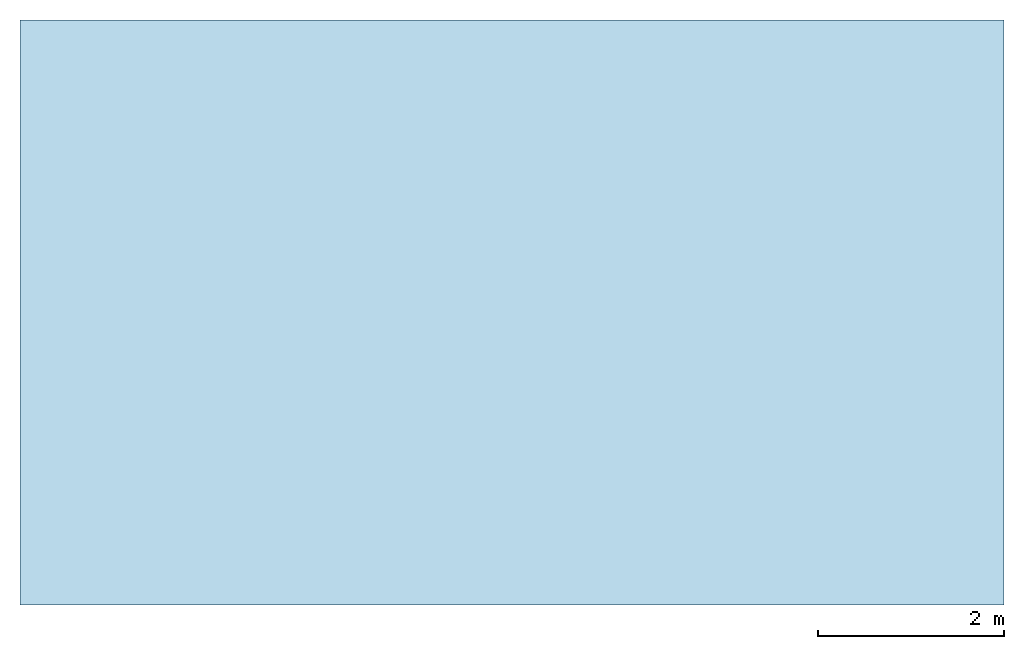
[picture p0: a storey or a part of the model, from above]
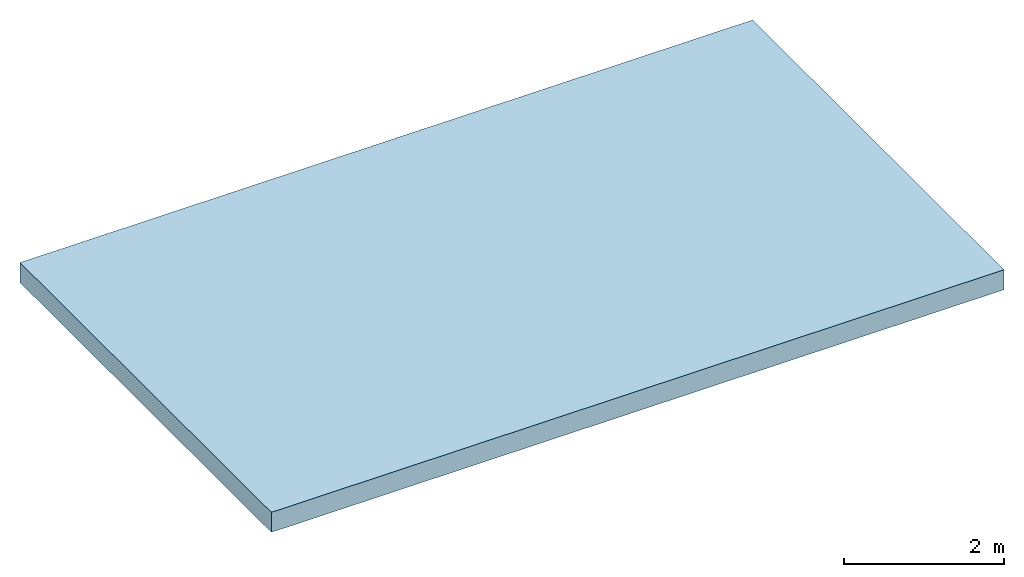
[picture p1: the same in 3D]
Properties of the parts of a building model (IFC2X3), part 1 of 2

# File
Description: ViewDefinition [CoordinationView_V2.0]
File name: Project Number
Time: 2019-01-10T09:33:45
Written by: The EXPRESS Data Manager Version 5.02.0100.07 : 28 Aug 2013
Made in: 20180216_1515(x64) - Exporter 19.0.0.405 - Alternate UI 19.0.0.405
Comment: STEP Physical File produced by: The EXPRESS Data Manager Version 5.02.0100.07 : 28 Aug 2013 * Module: EDMstepFileFactory/EDMstandAlone * Creation date: Thu Jan 10 09:33:45 2019 * Host: nimbus * Database: C:\Users\okonski\AppData\Local\Temp\{17E0146B-8E79-4994-994E-66D10485D688}\ifc * Database version: 5507 * Database creation date: Thu Jan 10 09:33:31 2019 * Schema: IFC2X3 * Model: DataRepository.ifc * Model creation date: Thu Jan 10 09:33:31 2019 * Header model: DataRepository.ifc_HeaderModel * Header model creation date: Thu Jan 10 09:33:31 2019 * EDMuser: sdai-user * EDMgroup: sdai-group * License ID and type: 5605 : Permanent license. Expiry date: * EDMstepFileFactory options: 020000

# IfcProject, Project Number
LongName: Project Name; Phase: Project Status

# IfcSite, Default
RefLatitude: 42, 21, 30, 344238; RefLongitude: -71, -3, -35, -194702; RefElevation: 0 ft

# IfcBuilding
Pset_BuildingCommon - NumberOfStoreys: 14

# IfcBuildingStorey (14)
Name | LongName | Elevation (ft)
Level 1 | Level 1 | 0
L 1 | L 1 | 5
Level 2 | Level 2 | 10
L 2 | L 2 | 15
L 3 | L 3 | 20
L 4 | L 4 | 25
L 5 | L 5 | 30
L 6 | L 6 | 35
L 7 | L 7 | 40
L 8 | L 8 | 45
L 9 | L 9 | 50
L 10 | L 10 | 55
L 11 | L 11 | 60
L 12 | L 12 | 69

# IfcBuildingElementProxy: 36" x 84" (36)
Type - Material: Door - Frame
Pset_BuildingElementProxyCommon - Reference: 36" x 84"
Name (Passage Opening-Cased:36" x 84":...) | In
199862 | Level 1
199918 | Level 1
199949 | Level 1
199975 | Level 1
199997 | Level 1
200042 | Level 1
202377 | Level 2
202378 | Level 2
202379 | Level 2
202380 | Level 2
202381 | Level 2
202382 | Level 2
204046 | L 3
204047 | L 3
204048 | L 3
204049 | L 3
204050 | L 3
204051 | L 3
204783 | L 5
204784 | L 5
204785 | L 5
204786 | L 5
204787 | L 5
204788 | L 5
205241 | L 7
205242 | L 7
205243 | L 7
205244 | L 7
205245 | L 7
205246 | L 7
205681 | L 9
205682 | L 9
205683 | L 9
205684 | L 9
205685 | L 9
205686 | L 9

# IfcColumn: 06" Diameter (2)
In: Level 1
Type - ElementType: 06" Diameter; PredefinedType: COLUMN; Classification: B1010200 Upper Floor Framing - Vertical Elements (Uniformat)
Pset_ColumnCommon - IsExternal: no; LoadBearing: no; Reference: 06" Diameter
Name (Round Column:06" Diameter:...)
209231 | Pset_ColumnCommon - Slope: 0 deg
209550

# IfcCurtainWall: Curtain Wall:Storefront, Curtain Wall:Storefront:194278
In: Level 1
Classification: B2020200 Curtain Walls (Uniformat)
Pset_CurtainWallCommon - IsExternal: yes; Reference: Storefront

# IfcCurtainWall: Curtain Wall:Storefront 2 (56)
Classification: B2020200 Curtain Walls (Uniformat)
Pset_CurtainWallCommon - IsExternal: yes; Reference: Storefront 2
Name (Curtain Wall:Storefront 2:...) | In | Group
196427 | Level 1 | Model Group:Group 3:200611
196767 | Level 1 | Model Group:Group 3:200611
196928 | Level 1 | Model Group:Group 3:200611
197503 | Level 1 | Model Group:Group 3:200611
197879 | Level 1 | Model Group:Group 3:200611
198087 | Level 1 | Model Group:Group 3:200611
198260 | Level 1 | Model Group:Group 3:200611
200148 | Level 1 | Model Group:Group 3:200611
200336 | Level 1 | Model Group:Group 3:200611
201495 | Level 2 | Model Group:Group 4:201905
201521 | Level 2 | Model Group:Group 4:201905
201547 | Level 2 | Model Group:Group 4:201905
201573 | Level 2 | Model Group:Group 4:201905
201599 | Level 2 | Model Group:Group 4:201905
201682 | Level 2 | Model Group:Group 4:201905
201717 | Level 2 | Model Group:Group 4:201905
201844 | Level 2 | Model Group:Group 4:201905
201879 | Level 2 | Model Group:Group 4:201905
203661 | L 3 | Model Group:Group 4:204045
203686 | L 3 | Model Group:Group 4:204045
203711 | L 3 | Model Group:Group 4:204045
203737 | L 3 | Model Group:Group 4:204045
203763 | L 3 | Model Group:Group 4:204045
203846 | L 3 | Model Group:Group 4:204045
203880 | L 3 | Model Group:Group 4:204045
203985 | L 3 | Model Group:Group 4:204045
204019 | L 3 | Model Group:Group 4:204045
204398 | L 5 | Model Group:Group 4:204782
204423 | L 5 | Model Group:Group 4:204782
204448 | L 5 | Model Group:Group 4:204782
204474 | L 5 | Model Group:Group 4:204782
204500 | L 5 | Model Group:Group 4:204782
204583 | L 5 | Model Group:Group 4:204782
204617 | L 5 | Model Group:Group 4:204782
204722 | L 5 | Model Group:Group 4:204782
204756 | L 5 | Model Group:Group 4:204782
204856 | L 7 | Model Group:Group 4:205240
204881 | L 7 | Model Group:Group 4:205240
204906 | L 7 | Model Group:Group 4:205240
204932 | L 7 | Model Group:Group 4:205240
204958 | L 7 | Model Group:Group 4:205240
205041 | L 7 | Model Group:Group 4:205240
205075 | L 7 | Model Group:Group 4:205240
205180 | L 7 | Model Group:Group 4:205240
205214 | L 7 | Model Group:Group 4:205240
205296 | L 9
205321 | L 9
205346 | L 9 | Model Group:Array Group 2:207312
205372 | L 9 | Model Group:Array Group 2:207312
205398 | L 9
205481 | L 9
205515 | L 9
205620 | L 9
205654 | L 9
207315 | L 11
207341 | L 11

# IfcGroup: Model Group:Group 4 (4)
Name (Model Group:Group 4:...) | Group
201905
204045 | Model Group:Array Group 1:204379
204782 | Model Group:Array Group 1:204817
205240 | Model Group:Array Group 1:205275

# IfcMember: 2.5" x 5" rectangular (1532)
Type - ElementType: 2.5" x 5" rectangular; PredefinedType: MEMBER
Classification: B2020200 Curtain Walls (Uniformat); Material: Aluminum
Pset_MemberCommon - LoadBearing: yes; IsExternal: yes; Reference: 2.5" x 5" rectangular
Name (Rectangular Mullion:2.5" x 5" rectangular:...) | In | Span (ft) | Group
194291 | Level 1 | 4.6875
194292 | Level 1 | 4.6875
194293 | Level 1 | 4.6875
194294 | Level 1 | 4.6875
194295 | Level 1 | 5
194296 | Level 1 | 5
194297 | Level 1 | 5
194298 | Level 1 | 3
194299 | Level 1 | 5
194300 | Level 1 | 5
194301 | Level 1 | 4.6875
194302 | Level 1 | 4.6875
194303 | Level 1 | 4.6875
194304 | Level 1 | 4.6875
194305 | Level 1 | 5
194306 | Level 1 | 5
194307 | Level 1 | 5
194373 | Level 1 | 5
194374 | Level 1 | 5
194375 | Level 1 | 5
194376 | Level 1 | 5
194377 | Level 1 | 5
194378 | Level 1 | 5
194379 | Level 1 | 5
194380 | Level 1 | 5
194381 | Level 1 | 5
194382 | Level 1 | 5
194383 | Level 1 | 5
194384 | Level 1 | 5
194385 | Level 1 | 5
194386 | Level 1 | 5
194387 | Level 1 | 5
194388 | Level 1 | 4.6875
194389 | Level 1 | 4.6875
194390 | Level 1 | 4.6875
194391 | Level 1 | 4.6875
194392 | Level 1 | 4.6875
194393 | Level 1 | 4.6875
194394 | Level 1 | 4.6875
194395 | Level 1 | 4.6875
194396 | Level 1 | 4.6875
194397 | Level 1 | 4.6875
194475 | Level 1 | 5
194476 | Level 1 | 5
194477 | Level 1 | 5
194478 | Level 1 | 5
194479 | Level 1 | 5
194480 | Level 1 | 5
194481 | Level 1 | 5
194482 | Level 1 | 5
194483 | Level 1 | 5
194484 | Level 1 | 5
194485 | Level 1 | 5
194486 | Level 1 | 5
194487 | Level 1 | 4.6875
194488 | Level 1 | 4.6875
194489 | Level 1 | 4.6875
194490 | Level 1 | 4.6875
194491 | Level 1 | 4.6875
194492 | Level 1 | 4.6875
194493 | Level 1 | 4.6875
194494 | Level 1 | 4.6875
206421 | Level 1 | 5
206422 | Level 1 | 5
206423 | Level 1 | 5
206424 | Level 1 | 3
206425 | Level 1 | 5
206426 | Level 1 | 3
206427 | Level 1 | 4.6875
206428 | Level 1 | 4.6875
206429 | Level 1 | 4.6875
206430 | Level 1 | 4.6875
196453 | Level 1 | 4.6875 | Model Group:Group 3:200611
196454 | Level 1 | 4.6875 | Model Group:Group 3:200611
196455 | Level 1 | 4.79167 | Model Group:Group 3:200611
196457 | Level 1 | 4.6875 | Model Group:Group 3:200611
196459 | Level 1 | 4.6875 | Model Group:Group 3:200611
196461 | Level 1 | 7 | Model Group:Group 3:200611
196462 | Level 1 | 2 | Model Group:Group 3:200611
196465 | Level 1 | 2 | Model Group:Group 3:200611
196466 | Level 1 | 7 | Model Group:Group 3:200611
196469 | Level 1 | 4.6875 | Model Group:Group 3:200611
196470 | Level 1 | 4.79167 | Model Group:Group 3:200611
196471 | Level 1 | 4.6875 | Model Group:Group 3:200611
196481 | Level 1 | 7 | Model Group:Group 3:200611
196482 | Level 1 | 7 | Model Group:Group 3:200611
196484 | Level 1 | 2 | Model Group:Group 3:200611
196485 | Level 1 | 2 | Model Group:Group 3:200611
196777 | Level 1 | 4.6875 | Model Group:Group 3:200611
196778 | Level 1 | 4.6875 | Model Group:Group 3:200611
196779 | Level 1 | 4.79167 | Model Group:Group 3:200611
196780 | Level 1 | 4.6875 | Model Group:Group 3:200611
196781 | Level 1 | 4.6875 | Model Group:Group 3:200611
196782 | Level 1 | 7 | Model Group:Group 3:200611
196783 | Level 1 | 2 | Model Group:Group 3:200611
196784 | Level 1 | 2 | Model Group:Group 3:200611
196785 | Level 1 | 7 | Model Group:Group 3:200611
196786 | Level 1 | 4.6875 | Model Group:Group 3:200611
196787 | Level 1 | 4.79167 | Model Group:Group 3:200611
196788 | Level 1 | 4.6875 | Model Group:Group 3:200611
196789 | Level 1 | 7 | Model Group:Group 3:200611
196790 | Level 1 | 7 | Model Group:Group 3:200611
196791 | Level 1 | 2 | Model Group:Group 3:200611
196792 | Level 1 | 2 | Model Group:Group 3:200611
196941 | Level 1 | 0.604167 | Model Group:Group 3:200611
196942 | Level 1 | 0.604167 | Model Group:Group 3:200611
196943 | Level 1 | 7 | Model Group:Group 3:200611
196944 | Level 1 | 2 | Model Group:Group 3:200611
196947 | Level 1 | 2 | Model Group:Group 3:200611
196948 | Level 1 | 7 | Model Group:Group 3:200611
196951 | Level 1 | 0.604167 | Model Group:Group 3:200611
197210 | Level 1 | 0.604167 | Model Group:Group 3:200611
197212 | Level 1 | 2.79167 | Model Group:Group 3:200611
197213 | Level 1 | 7 | Model Group:Group 3:200611
197214 | Level 1 | 2 | Model Group:Group 3:200611
197342 | Level 1 | 2.79167 | Model Group:Group 3:200611
197343 | Level 1 | 0.604167 | Model Group:Group 3:200611
197344 | Level 1 | 0.604167 | Model Group:Group 3:200611
197345 | Level 1 | 7 | Model Group:Group 3:200611
197346 | Level 1 | 2 | Model Group:Group 3:200611
197507 | Level 1 | 0.604167 | Model Group:Group 3:200611
197508 | Level 1 | 0.604167 | Model Group:Group 3:200611
197509 | Level 1 | 7 | Model Group:Group 3:200611
197510 | Level 1 | 2 | Model Group:Group 3:200611
197511 | Level 1 | 2 | Model Group:Group 3:200611
197512 | Level 1 | 7 | Model Group:Group 3:200611
197513 | Level 1 | 0.604167 | Model Group:Group 3:200611
197517 | Level 1 | 0.604167 | Model Group:Group 3:200611
197518 | Level 1 | 2.79167 | Model Group:Group 3:200611
197519 | Level 1 | 7 | Model Group:Group 3:200611
197520 | Level 1 | 2 | Model Group:Group 3:200611
197524 | Level 1 | 2.79167 | Model Group:Group 3:200611
197525 | Level 1 | 0.604167 | Model Group:Group 3:200611
197526 | Level 1 | 0.604167 | Model Group:Group 3:200611
197527 | Level 1 | 7 | Model Group:Group 3:200611
197528 | Level 1 | 2 | Model Group:Group 3:200611
197913 | Level 1 | 4.29514 | Model Group:Group 3:200611
197914 | Level 1 | 4.29514 | Model Group:Group 3:200611
197915 | Level 1 | 4.39931 | Model Group:Group 3:200611
197916 | Level 1 | 4.39931 | Model Group:Group 3:200611
197917 | Level 1 | 4.39931 | Model Group:Group 3:200611
197918 | Level 1 | 4.39931 | Model Group:Group 3:200611
197919 | Level 1 | 4.39931 | Model Group:Group 3:200611
197920 | Level 1 | 4.39931 | Model Group:Group 3:200611
197921 | Level 1 | 4.39931 | Model Group:Group 3:200611
197922 | Level 1 | 4.39931 | Model Group:Group 3:200611
197923 | Level 1 | 4.29514 | Model Group:Group 3:200611
197924 | Level 1 | 4.39931 | Model Group:Group 3:200611
197925 | Level 1 | 4.39931 | Model Group:Group 3:200611
197926 | Level 1 | 4.39931 | Model Group:Group 3:200611
197927 | Level 1 | 4.39931 | Model Group:Group 3:200611
197928 | Level 1 | 4.39931 | Model Group:Group 3:200611
197929 | Level 1 | 4.39931 | Model Group:Group 3:200611
197930 | Level 1 | 4.39931 | Model Group:Group 3:200611
197931 | Level 1 | 4.39931 | Model Group:Group 3:200611
197932 | Level 1 | 4.39931 | Model Group:Group 3:200611
197933 | Level 1 | 7 | Model Group:Group 3:200611
197934 | Level 1 | 2 | Model Group:Group 3:200611
197935 | Level 1 | 2 | Model Group:Group 3:200611
197936 | Level 1 | 7 | Model Group:Group 3:200611
197937 | Level 1 | 4.29514 | Model Group:Group 3:200611
197938 | Level 1 | 4.39931 | Model Group:Group 3:200611
197939 | Level 1 | 4.39931 | Model Group:Group 3:200611
197940 | Level 1 | 4.39931 | Model Group:Group 3:200611
197941 | Level 1 | 4.39931 | Model Group:Group 3:200611
197942 | Level 1 | 4.39931 | Model Group:Group 3:200611
197943 | Level 1 | 4.39931 | Model Group:Group 3:200611
197944 | Level 1 | 4.39931 | Model Group:Group 3:200611
197945 | Level 1 | 4.39931 | Model Group:Group 3:200611
197946 | Level 1 | 4.39931 | Model Group:Group 3:200611
197947 | Level 1 | 7 | Model Group:Group 3:200611
197948 | Level 1 | 7 | Model Group:Group 3:200611
197949 | Level 1 | 7 | Model Group:Group 3:200611
197950 | Level 1 | 7 | Model Group:Group 3:200611
197951 | Level 1 | 7 | Model Group:Group 3:200611
197952 | Level 1 | 7 | Model Group:Group 3:200611
197953 | Level 1 | 7 | Model Group:Group 3:200611
197954 | Level 1 | 7 | Model Group:Group 3:200611
197955 | Level 1 | 7 | Model Group:Group 3:200611
197956 | Level 1 | 2 | Model Group:Group 3:200611
197957 | Level 1 | 2 | Model Group:Group 3:200611
197958 | Level 1 | 2 | Model Group:Group 3:200611
197959 | Level 1 | 2 | Model Group:Group 3:200611
197960 | Level 1 | 2 | Model Group:Group 3:200611
197961 | Level 1 | 2 | Model Group:Group 3:200611
197962 | Level 1 | 2 | Model Group:Group 3:200611
197963 | Level 1 | 2 | Model Group:Group 3:200611
197964 | Level 1 | 2 | Model Group:Group 3:200611
198397 | Level 1 | 4.39931 | Model Group:Group 3:200611
198398 | Level 1 | 4.39931 | Model Group:Group 3:200611
198399 | Level 1 | 4.39931 | Model Group:Group 3:200611
198400 | Level 1 | 7 | Model Group:Group 3:200611
198401 | Level 1 | 2 | Model Group:Group 3:200611
198473 | Level 1 | 4.39931 | Model Group:Group 3:200611
198474 | Level 1 | 4.29514 | Model Group:Group 3:200611
198475 | Level 1 | 4.29514 | Model Group:Group 3:200611
198476 | Level 1 | 7 | Model Group:Group 3:200611
198477 | Level 1 | 2 | Model Group:Group 3:200611
198124 | Level 1 | 4.6572 | Model Group:Group 3:200611
198125 | Level 1 | 4.6572 | Model Group:Group 3:200611
198126 | Level 1 | 4.76136 | Model Group:Group 3:200611
198127 | Level 1 | 4.76136 | Model Group:Group 3:200611
198135 | Level 1 | 4.6572 | Model Group:Group 3:200611
198136 | Level 1 | 4.76136 | Model Group:Group 3:200611
198137 | Level 1 | 4.76136 | Model Group:Group 3:200611
198138 | Level 1 | 4.6572 | Model Group:Group 3:200611
198146 | Level 1 | 7 | Model Group:Group 3:200611
198147 | Level 1 | 2 | Model Group:Group 3:200611
198148 | Level 1 | 2 | Model Group:Group 3:200611
198149 | Level 1 | 7 | Model Group:Group 3:200611
198150 | Level 1 | 4.6572 | Model Group:Group 3:200611
198151 | Level 1 | 4.76136 | Model Group:Group 3:200611
198152 | Level 1 | 4.76136 | Model Group:Group 3:200611
198153 | Level 1 | 4.6572 | Model Group:Group 3:200611
198161 | Level 1 | 7 | Model Group:Group 3:200611
198162 | Level 1 | 7 | Model Group:Group 3:200611
198163 | Level 1 | 7 | Model Group:Group 3:200611
198171 | Level 1 | 2 | Model Group:Group 3:200611
198172 | Level 1 | 2 | Model Group:Group 3:200611
198173 | Level 1 | 2 | Model Group:Group 3:200611
198294 | Level 1 | 4.29514 | Model Group:Group 3:200611
198295 | Level 1 | 4.29514 | Model Group:Group 3:200611
198296 | Level 1 | 4.39931 | Model Group:Group 3:200611
198297 | Level 1 | 4.39931 | Model Group:Group 3:200611
198298 | Level 1 | 4.39931 | Model Group:Group 3:200611
198299 | Level 1 | 4.39931 | Model Group:Group 3:200611
198300 | Level 1 | 4.39931 | Model Group:Group 3:200611
198301 | Level 1 | 4.39931 | Model Group:Group 3:200611
198302 | Level 1 | 4.39931 | Model Group:Group 3:200611
198303 | Level 1 | 4.39931 | Model Group:Group 3:200611
198304 | Level 1 | 4.29514 | Model Group:Group 3:200611
198305 | Level 1 | 4.39931 | Model Group:Group 3:200611
198306 | Level 1 | 4.39931 | Model Group:Group 3:200611
198307 | Level 1 | 4.39931 | Model Group:Group 3:200611
198308 | Level 1 | 4.39931 | Model Group:Group 3:200611
198309 | Level 1 | 4.39931 | Model Group:Group 3:200611
198310 | Level 1 | 4.39931 | Model Group:Group 3:200611
198311 | Level 1 | 4.39931 | Model Group:Group 3:200611
198312 | Level 1 | 4.39931 | Model Group:Group 3:200611
198313 | Level 1 | 4.39931 | Model Group:Group 3:200611
198314 | Level 1 | 7 | Model Group:Group 3:200611
198315 | Level 1 | 2 | Model Group:Group 3:200611
198316 | Level 1 | 2 | Model Group:Group 3:200611
198317 | Level 1 | 7 | Model Group:Group 3:200611
198318 | Level 1 | 4.29514 | Model Group:Group 3:200611
198319 | Level 1 | 4.39931 | Model Group:Group 3:200611
198320 | Level 1 | 4.39931 | Model Group:Group 3:200611
198321 | Level 1 | 4.39931 | Model Group:Group 3:200611
198322 | Level 1 | 4.39931 | Model Group:Group 3:200611
198323 | Level 1 | 4.39931 | Model Group:Group 3:200611
198324 | Level 1 | 4.39931 | Model Group:Group 3:200611
198325 | Level 1 | 4.39931 | Model Group:Group 3:200611
198326 | Level 1 | 4.39931 | Model Group:Group 3:200611
198327 | Level 1 | 4.39931 | Model Group:Group 3:200611
198328 | Level 1 | 7 | Model Group:Group 3:200611
198329 | Level 1 | 7 | Model Group:Group 3:200611
198330 | Level 1 | 7 | Model Group:Group 3:200611
198331 | Level 1 | 7 | Model Group:Group 3:200611
198332 | Level 1 | 7 | Model Group:Group 3:200611
198333 | Level 1 | 7 | Model Group:Group 3:200611
198334 | Level 1 | 7 | Model Group:Group 3:200611
198335 | Level 1 | 7 | Model Group:Group 3:200611
198336 | Level 1 | 7 | Model Group:Group 3:200611
198337 | Level 1 | 2 | Model Group:Group 3:200611
198338 | Level 1 | 2 | Model Group:Group 3:200611
198339 | Level 1 | 2 | Model Group:Group 3:200611
198340 | Level 1 | 2 | Model Group:Group 3:200611
198341 | Level 1 | 2 | Model Group:Group 3:200611
198342 | Level 1 | 2 | Model Group:Group 3:200611
198343 | Level 1 | 2 | Model Group:Group 3:200611
198344 | Level 1 | 2 | Model Group:Group 3:200611
198345 | Level 1 | 2 | Model Group:Group 3:200611
198402 | Level 1 | 4.39931 | Model Group:Group 3:200611
198403 | Level 1 | 4.39931 | Model Group:Group 3:200611
198404 | Level 1 | 4.39931 | Model Group:Group 3:200611
198405 | Level 1 | 7 | Model Group:Group 3:200611
198406 | Level 1 | 2 | Model Group:Group 3:200611
198478 | Level 1 | 4.39931 | Model Group:Group 3:200611
198479 | Level 1 | 4.29514 | Model Group:Group 3:200611
198480 | Level 1 | 4.29514 | Model Group:Group 3:200611
198481 | Level 1 | 7 | Model Group:Group 3:200611
198482 | Level 1 | 2 | Model Group:Group 3:200611
200161 | Level 1 | 4.6572 | Model Group:Group 3:200611
200162 | Level 1 | 4.6572 | Model Group:Group 3:200611
200163 | Level 1 | 4.76136 | Model Group:Group 3:200611
200164 | Level 1 | 4.76136 | Model Group:Group 3:200611
200165 | Level 1 | 4.6572 | Model Group:Group 3:200611
200166 | Level 1 | 4.76136 | Model Group:Group 3:200611
200167 | Level 1 | 4.76136 | Model Group:Group 3:200611
200168 | Level 1 | 4.6572 | Model Group:Group 3:200611
200169 | Level 1 | 7 | Model Group:Group 3:200611
200170 | Level 1 | 2 | Model Group:Group 3:200611
200171 | Level 1 | 2 | Model Group:Group 3:200611
200172 | Level 1 | 7 | Model Group:Group 3:200611
200173 | Level 1 | 4.6572 | Model Group:Group 3:200611
200174 | Level 1 | 4.76136 | Model Group:Group 3:200611
200175 | Level 1 | 4.76136 | Model Group:Group 3:200611
200176 | Level 1 | 4.6572 | Model Group:Group 3:200611
200177 | Level 1 | 7 | Model Group:Group 3:200611
200178 | Level 1 | 7 | Model Group:Group 3:200611
200179 | Level 1 | 7 | Model Group:Group 3:200611
200180 | Level 1 | 2 | Model Group:Group 3:200611
200181 | Level 1 | 2 | Model Group:Group 3:200611
200182 | Level 1 | 2 | Model Group:Group 3:200611
200351 | Level 1 | 4.49053 | Model Group:Group 3:200611
200352 | Level 1 | 4.49053 | Model Group:Group 3:200611
200353 | Level 1 | 4.5947 | Model Group:Group 3:200611
200354 | Level 1 | 4.49053 | Model Group:Group 3:200611
200356 | Level 1 | 4.49053 | Model Group:Group 3:200611
200357 | Level 1 | 7 | Model Group:Group 3:200611
200358 | Level 1 | 2 | Model Group:Group 3:200611
200359 | Level 1 | 2 | Model Group:Group 3:200611
200360 | Level 1 | 7 | Model Group:Group 3:200611
200361 | Level 1 | 4.49053 | Model Group:Group 3:200611
200362 | Level 1 | 4.5947 | Model Group:Group 3:200611
200363 | Level 1 | 4.49053 | Model Group:Group 3:200611
200364 | Level 1 | 7 | Model Group:Group 3:200611
200365 | Level 1 | 7 | Model Group:Group 3:200611
200366 | Level 1 | 2 | Model Group:Group 3:200611
200367 | Level 1 | 2 | Model Group:Group 3:200611
201505 | Level 2 | 4.6875 | Model Group:Group 4:201905
201506 | Level 2 | 4.6875 | Model Group:Group 4:201905
201507 | Level 2 | 4.79167 | Model Group:Group 4:201905
201509 | Level 2 | 4.6875 | Model Group:Group 4:201905
201510 | Level 2 | 7 | Model Group:Group 4:201905
201511 | Level 2 | 2 | Model Group:Group 4:201905
201512 | Level 2 | 2 | Model Group:Group 4:201905
201513 | Level 2 | 7 | Model Group:Group 4:201905
201514 | Level 2 | 4.6875 | Model Group:Group 4:201905
201515 | Level 2 | 4.79167 | Model Group:Group 4:201905
201516 | Level 2 | 4.6875 | Model Group:Group 4:201905
201517 | Level 2 | 7 | Model Group:Group 4:201905
201518 | Level 2 | 7 | Model Group:Group 4:201905
201519 | Level 2 | 2 | Model Group:Group 4:201905
201520 | Level 2 | 2 | Model Group:Group 4:201905
203381 | Level 2 | 4.79167 | Model Group:Group 4:201905
201531 | Level 2 | 4.6875 | Model Group:Group 4:201905
201532 | Level 2 | 4.6875 | Model Group:Group 4:201905
201533 | Level 2 | 4.79167 | Model Group:Group 4:201905
201534 | Level 2 | 4.6875 | Model Group:Group 4:201905
201536 | Level 2 | 7 | Model Group:Group 4:201905
201537 | Level 2 | 2 | Model Group:Group 4:201905
201538 | Level 2 | 2 | Model Group:Group 4:201905
201539 | Level 2 | 7 | Model Group:Group 4:201905
201540 | Level 2 | 4.6875 | Model Group:Group 4:201905
201541 | Level 2 | 4.79167 | Model Group:Group 4:201905
201542 | Level 2 | 4.6875 | Model Group:Group 4:201905
201543 | Level 2 | 7 | Model Group:Group 4:201905
201544 | Level 2 | 7 | Model Group:Group 4:201905
201545 | Level 2 | 2 | Model Group:Group 4:201905
201546 | Level 2 | 2 | Model Group:Group 4:201905
203378 | Level 2 | 4.79167 | Model Group:Group 4:201905
201551 | Level 2 | 0.604167 | Model Group:Group 4:201905
201552 | Level 2 | 0.604167 | Model Group:Group 4:201905
201553 | Level 2 | 7 | Model Group:Group 4:201905
201554 | Level 2 | 2 | Model Group:Group 4:201905
201555 | Level 2 | 2 | Model Group:Group 4:201905
201556 | Level 2 | 7 | Model Group:Group 4:201905
201557 | Level 2 | 0.604167 | Model Group:Group 4:201905
201561 | Level 2 | 0.604167 | Model Group:Group 4:201905
201562 | Level 2 | 2.79167 | Model Group:Group 4:201905
201563 | Level 2 | 7 | Model Group:Group 4:201905
201564 | Level 2 | 2 | Model Group:Group 4:201905
201568 | Level 2 | 2.79167 | Model Group:Group 4:201905
201569 | Level 2 | 0.604167 | Model Group:Group 4:201905
201570 | Level 2 | 0.604167 | Model Group:Group 4:201905
201571 | Level 2 | 7 | Model Group:Group 4:201905
201572 | Level 2 | 2 | Model Group:Group 4:201905
201577 | Level 2 | 0.604167 | Model Group:Group 4:201905
201578 | Level 2 | 0.604167 | Model Group:Group 4:201905
201579 | Level 2 | 7 | Model Group:Group 4:201905
201580 | Level 2 | 2 | Model Group:Group 4:201905
201581 | Level 2 | 2 | Model Group:Group 4:201905
201582 | Level 2 | 7 | Model Group:Group 4:201905
201583 | Level 2 | 0.604167 | Model Group:Group 4:201905
201587 | Level 2 | 0.604167 | Model Group:Group 4:201905
201588 | Level 2 | 2.79167 | Model Group:Group 4:201905
201589 | Level 2 | 7 | Model Group:Group 4:201905
201590 | Level 2 | 2 | Model Group:Group 4:201905
201594 | Level 2 | 2.79167 | Model Group:Group 4:201905
201595 | Level 2 | 0.604167 | Model Group:Group 4:201905
201596 | Level 2 | 0.604167 | Model Group:Group 4:201905
201597 | Level 2 | 7 | Model Group:Group 4:201905
201598 | Level 2 | 2 | Model Group:Group 4:201905
201630 | Level 2 | 4.25947 | Model Group:Group 4:201905
201631 | Level 2 | 4.25947 | Model Group:Group 4:201905
201632 | Level 2 | 4.36364 | Model Group:Group 4:201905
201633 | Level 2 | 4.36364 | Model Group:Group 4:201905
201634 | Level 2 | 4.36364 | Model Group:Group 4:201905
201635 | Level 2 | 4.36364 | Model Group:Group 4:201905
201636 | Level 2 | 4.36364 | Model Group:Group 4:201905
201637 | Level 2 | 4.36364 | Model Group:Group 4:201905
201638 | Level 2 | 4.36364 | Model Group:Group 4:201905
201639 | Level 2 | 4.36364 | Model Group:Group 4:201905
201640 | Level 2 | 4.25947 | Model Group:Group 4:201905
201641 | Level 2 | 4.36364 | Model Group:Group 4:201905
201642 | Level 2 | 4.36364 | Model Group:Group 4:201905
201643 | Level 2 | 4.36364 | Model Group:Group 4:201905
201644 | Level 2 | 4.36364 | Model Group:Group 4:201905
201645 | Level 2 | 4.36364 | Model Group:Group 4:201905
201646 | Level 2 | 4.36364 | Model Group:Group 4:201905
201647 | Level 2 | 4.36364 | Model Group:Group 4:201905
201648 | Level 2 | 4.36364 | Model Group:Group 4:201905
201649 | Level 2 | 4.36364 | Model Group:Group 4:201905
201650 | Level 2 | 7 | Model Group:Group 4:201905
201651 | Level 2 | 2 | Model Group:Group 4:201905
201652 | Level 2 | 2 | Model Group:Group 4:201905
201653 | Level 2 | 7 | Model Group:Group 4:201905
201654 | Level 2 | 4.25947 | Model Group:Group 4:201905
201655 | Level 2 | 4.36364 | Model Group:Group 4:201905
201656 | Level 2 | 4.36364 | Model Group:Group 4:201905
201657 | Level 2 | 4.36364 | Model Group:Group 4:201905
201658 | Level 2 | 4.36364 | Model Group:Group 4:201905
201659 | Level 2 | 4.36364 | Model Group:Group 4:201905
201660 | Level 2 | 4.36364 | Model Group:Group 4:201905
201661 | Level 2 | 4.36364 | Model Group:Group 4:201905
201662 | Level 2 | 4.36364 | Model Group:Group 4:201905
201663 | Level 2 | 4.36364 | Model Group:Group 4:201905
201664 | Level 2 | 7 | Model Group:Group 4:201905
201665 | Level 2 | 7 | Model Group:Group 4:201905
201666 | Level 2 | 7 | Model Group:Group 4:201905
201667 | Level 2 | 7 | Model Group:Group 4:201905
201668 | Level 2 | 7 | Model Group:Group 4:201905
201669 | Level 2 | 7 | Model Group:Group 4:201905
201670 | Level 2 | 7 | Model Group:Group 4:201905
201671 | Level 2 | 7 | Model Group:Group 4:201905
201672 | Level 2 | 7 | Model Group:Group 4:201905
201673 | Level 2 | 2 | Model Group:Group 4:201905
201674 | Level 2 | 2 | Model Group:Group 4:201905
201675 | Level 2 | 2 | Model Group:Group 4:201905
201676 | Level 2 | 2 | Model Group:Group 4:201905
201677 | Level 2 | 2 | Model Group:Group 4:201905
201678 | Level 2 | 2 | Model Group:Group 4:201905
201679 | Level 2 | 2 | Model Group:Group 4:201905
201680 | Level 2 | 2 | Model Group:Group 4:201905
201681 | Level 2 | 2 | Model Group:Group 4:201905
201806 | Level 2 | 4.36364 | Model Group:Group 4:201905
201807 | Level 2 | 4.25947 | Model Group:Group 4:201905
201808 | Level 2 | 4.25947 | Model Group:Group 4:201905
201809 | Level 2 | 7 | Model Group:Group 4:201905
201810 | Level 2 | 2 | Model Group:Group 4:201905
201695 | Level 2 | 4.5947 | Model Group:Group 4:201905
201696 | Level 2 | 4.5947 | Model Group:Group 4:201905
201697 | Level 2 | 4.69886 | Model Group:Group 4:201905
201698 | Level 2 | 4.69886 | Model Group:Group 4:201905
201699 | Level 2 | 4.5947 | Model Group:Group 4:201905
201701 | Level 2 | 4.69886 | Model Group:Group 4:201905
201702 | Level 2 | 4.5947 | Model Group:Group 4:201905
201703 | Level 2 | 7 | Model Group:Group 4:201905
201704 | Level 2 | 2 | Model Group:Group 4:201905
201705 | Level 2 | 2 | Model Group:Group 4:201905
201706 | Level 2 | 7 | Model Group:Group 4:201905
201707 | Level 2 | 4.5947 | Model Group:Group 4:201905
201708 | Level 2 | 4.69886 | Model Group:Group 4:201905
201709 | Level 2 | 4.69886 | Model Group:Group 4:201905
201710 | Level 2 | 4.5947 | Model Group:Group 4:201905
201711 | Level 2 | 7 | Model Group:Group 4:201905
201712 | Level 2 | 7 | Model Group:Group 4:201905
201713 | Level 2 | 7 | Model Group:Group 4:201905
201714 | Level 2 | 2 | Model Group:Group 4:201905
201715 | Level 2 | 2 | Model Group:Group 4:201905
201716 | Level 2 | 2 | Model Group:Group 4:201905
201748 | Level 2 | 4.25947 | Model Group:Group 4:201905
201749 | Level 2 | 4.25947 | Model Group:Group 4:201905
201750 | Level 2 | 4.36364 | Model Group:Group 4:201905
201751 | Level 2 | 4.36364 | Model Group:Group 4:201905
201752 | Level 2 | 4.36364 | Model Group:Group 4:201905
201753 | Level 2 | 4.36364 | Model Group:Group 4:201905
201754 | Level 2 | 4.36364 | Model Group:Group 4:201905
201755 | Level 2 | 4.36364 | Model Group:Group 4:201905
201756 | Level 2 | 4.36364 | Model Group:Group 4:201905
201757 | Level 2 | 4.36364 | Model Group:Group 4:201905
201758 | Level 2 | 4.25947 | Model Group:Group 4:201905
201759 | Level 2 | 4.36364 | Model Group:Group 4:201905
201760 | Level 2 | 4.36364 | Model Group:Group 4:201905
201761 | Level 2 | 4.36364 | Model Group:Group 4:201905
201762 | Level 2 | 4.36364 | Model Group:Group 4:201905
201763 | Level 2 | 4.36364 | Model Group:Group 4:201905
201764 | Level 2 | 4.36364 | Model Group:Group 4:201905
201765 | Level 2 | 4.36364 | Model Group:Group 4:201905
201766 | Level 2 | 4.36364 | Model Group:Group 4:201905
201767 | Level 2 | 4.36364 | Model Group:Group 4:201905
201768 | Level 2 | 7 | Model Group:Group 4:201905
201769 | Level 2 | 2 | Model Group:Group 4:201905
201770 | Level 2 | 2 | Model Group:Group 4:201905
201771 | Level 2 | 7 | Model Group:Group 4:201905
201772 | Level 2 | 4.25947 | Model Group:Group 4:201905
201773 | Level 2 | 4.36364 | Model Group:Group 4:201905
201774 | Level 2 | 4.36364 | Model Group:Group 4:201905
201775 | Level 2 | 4.36364 | Model Group:Group 4:201905
201776 | Level 2 | 4.36364 | Model Group:Group 4:201905
201777 | Level 2 | 4.36364 | Model Group:Group 4:201905
201778 | Level 2 | 4.36364 | Model Group:Group 4:201905
201779 | Level 2 | 4.36364 | Model Group:Group 4:201905
201780 | Level 2 | 4.36364 | Model Group:Group 4:201905
201781 | Level 2 | 4.36364 | Model Group:Group 4:201905
201782 | Level 2 | 7 | Model Group:Group 4:201905
201783 | Level 2 | 7 | Model Group:Group 4:201905
201784 | Level 2 | 7 | Model Group:Group 4:201905
201785 | Level 2 | 7 | Model Group:Group 4:201905
201786 | Level 2 | 7 | Model Group:Group 4:201905
201787 | Level 2 | 7 | Model Group:Group 4:201905
201788 | Level 2 | 7 | Model Group:Group 4:201905
201789 | Level 2 | 7 | Model Group:Group 4:201905
201790 | Level 2 | 7 | Model Group:Group 4:201905
201791 | Level 2 | 2 | Model Group:Group 4:201905
201792 | Level 2 | 2 | Model Group:Group 4:201905
201793 | Level 2 | 2 | Model Group:Group 4:201905
201794 | Level 2 | 2 | Model Group:Group 4:201905
201795 | Level 2 | 2 | Model Group:Group 4:201905
201796 | Level 2 | 2 | Model Group:Group 4:201905
201797 | Level 2 | 2 | Model Group:Group 4:201905
201798 | Level 2 | 2 | Model Group:Group 4:201905
201799 | Level 2 | 2 | Model Group:Group 4:201905
201811 | Level 2 | 4.36364 | Model Group:Group 4:201905
201812 | Level 2 | 4.25947 | Model Group:Group 4:201905
201813 | Level 2 | 4.25947 | Model Group:Group 4:201905
201814 | Level 2 | 7 | Model Group:Group 4:201905
201815 | Level 2 | 2 | Model Group:Group 4:201905
201857 | Level 2 | 4.5947 | Model Group:Group 4:201905
201858 | Level 2 | 4.5947 | Model Group:Group 4:201905
201859 | Level 2 | 4.69886 | Model Group:Group 4:201905
201860 | Level 2 | 4.69886 | Model Group:Group 4:201905
201861 | Level 2 | 4.5947 | Model Group:Group 4:201905
201862 | Level 2 | 4.69886 | Model Group:Group 4:201905
201864 | Level 2 | 4.5947 | Model Group:Group 4:201905
201865 | Level 2 | 7 | Model Group:Group 4:201905
201866 | Level 2 | 2 | Model Group:Group 4:201905
201867 | Level 2 | 2 | Model Group:Group 4:201905
201868 | Level 2 | 7 | Model Group:Group 4:201905
201869 | Level 2 | 4.5947 | Model Group:Group 4:201905
201870 | Level 2 | 4.69886 | Model Group:Group 4:201905
201871 | Level 2 | 4.69886 | Model Group:Group 4:201905
201872 | Level 2 | 4.5947 | Model Group:Group 4:201905
201873 | Level 2 | 7 | Model Group:Group 4:201905
201874 | Level 2 | 7 | Model Group:Group 4:201905
201875 | Level 2 | 7 | Model Group:Group 4:201905
201876 | Level 2 | 2 | Model Group:Group 4:201905
201877 | Level 2 | 2 | Model Group:Group 4:201905
201878 | Level 2 | 2 | Model Group:Group 4:201905
201889 | Level 2 | 4.49053 | Model Group:Group 4:201905
201890 | Level 2 | 4.49053 | Model Group:Group 4:201905
201891 | Level 2 | 4.5947 | Model Group:Group 4:201905
201892 | Level 2 | 4.49053 | Model Group:Group 4:201905
201893 | Level 2 | 4.49053 | Model Group:Group 4:201905
201894 | Level 2 | 7 | Model Group:Group 4:201905
201895 | Level 2 | 2 | Model Group:Group 4:201905
201896 | Level 2 | 2 | Model Group:Group 4:201905
201897 | Level 2 | 7 | Model Group:Group 4:201905
201898 | Level 2 | 4.49053 | Model Group:Group 4:201905
201899 | Level 2 | 4.5947 | Model Group:Group 4:201905
201900 | Level 2 | 4.49053 | Model Group:Group 4:201905
201901 | Level 2 | 7 | Model Group:Group 4:201905
201902 | Level 2 | 7 | Model Group:Group 4:201905
201903 | Level 2 | 2 | Model Group:Group 4:201905
201904 | Level 2 | 2 | Model Group:Group 4:201905
203671 | L 3 | 4.6875 | Model Group:Group 4:204045
203672 | L 3 | 4.6875 | Model Group:Group 4:204045
203673 | L 3 | 4.79167 | Model Group:Group 4:204045
203674 | L 3 | 4.6875 | Model Group:Group 4:204045
203675 | L 3 | 7 | Model Group:Group 4:204045
203676 | L 3 | 2 | Model Group:Group 4:204045
203677 | L 3 | 2 | Model Group:Group 4:204045
203678 | L 3 | 7 | Model Group:Group 4:204045
203679 | L 3 | 4.6875 | Model Group:Group 4:204045
203680 | L 3 | 4.79167 | Model Group:Group 4:204045
203681 | L 3 | 4.6875 | Model Group:Group 4:204045
203682 | L 3 | 7 | Model Group:Group 4:204045
203683 | L 3 | 7 | Model Group:Group 4:204045
203684 | L 3 | 2 | Model Group:Group 4:204045
203685 | L 3 | 2 | Model Group:Group 4:204045
204079 | L 3 | 4.79167 | Model Group:Group 4:204045
203696 | L 3 | 4.6875 | Model Group:Group 4:204045
203697 | L 3 | 4.6875 | Model Group:Group 4:204045
203698 | L 3 | 4.79167 | Model Group:Group 4:204045
203699 | L 3 | 4.6875 | Model Group:Group 4:204045
203700 | L 3 | 7 | Model Group:Group 4:204045
203701 | L 3 | 2 | Model Group:Group 4:204045
203702 | L 3 | 2 | Model Group:Group 4:204045
203703 | L 3 | 7 | Model Group:Group 4:204045
203704 | L 3 | 4.6875 | Model Group:Group 4:204045
203705 | L 3 | 4.79167 | Model Group:Group 4:204045
203706 | L 3 | 4.6875 | Model Group:Group 4:204045
203707 | L 3 | 7 | Model Group:Group 4:204045
203708 | L 3 | 7 | Model Group:Group 4:204045
203709 | L 3 | 2 | Model Group:Group 4:204045
203710 | L 3 | 2 | Model Group:Group 4:204045
204078 | L 3 | 4.79167 | Model Group:Group 4:204045
203715 | L 3 | 0.604167 | Model Group:Group 4:204045
203716 | L 3 | 0.604167 | Model Group:Group 4:204045
203717 | L 3 | 7 | Model Group:Group 4:204045
203718 | L 3 | 2 | Model Group:Group 4:204045
203719 | L 3 | 2 | Model Group:Group 4:204045
203720 | L 3 | 7 | Model Group:Group 4:204045
203721 | L 3 | 0.604167 | Model Group:Group 4:204045
203725 | L 3 | 0.604167 | Model Group:Group 4:204045
203726 | L 3 | 2.79167 | Model Group:Group 4:204045
203727 | L 3 | 7 | Model Group:Group 4:204045
203728 | L 3 | 2 | Model Group:Group 4:204045
203732 | L 3 | 2.79167 | Model Group:Group 4:204045
203733 | L 3 | 0.604167 | Model Group:Group 4:204045
203734 | L 3 | 0.604167 | Model Group:Group 4:204045
203735 | L 3 | 7 | Model Group:Group 4:204045
203736 | L 3 | 2 | Model Group:Group 4:204045
203741 | L 3 | 0.604167 | Model Group:Group 4:204045
203742 | L 3 | 0.604167 | Model Group:Group 4:204045
203743 | L 3 | 7 | Model Group:Group 4:204045
203744 | L 3 | 2 | Model Group:Group 4:204045
203745 | L 3 | 2 | Model Group:Group 4:204045
203746 | L 3 | 7 | Model Group:Group 4:204045
203747 | L 3 | 0.604167 | Model Group:Group 4:204045
203751 | L 3 | 0.604167 | Model Group:Group 4:204045
203752 | L 3 | 2.79167 | Model Group:Group 4:204045
203753 | L 3 | 7 | Model Group:Group 4:204045
203754 | L 3 | 2 | Model Group:Group 4:204045
203758 | L 3 | 2.79167 | Model Group:Group 4:204045
203759 | L 3 | 0.604167 | Model Group:Group 4:204045
203760 | L 3 | 0.604167 | Model Group:Group 4:204045
203761 | L 3 | 7 | Model Group:Group 4:204045
203762 | L 3 | 2 | Model Group:Group 4:204045
203794 | L 3 | 4.25947 | Model Group:Group 4:204045
203795 | L 3 | 4.25947 | Model Group:Group 4:204045
203796 | L 3 | 4.36364 | Model Group:Group 4:204045
203797 | L 3 | 4.36364 | Model Group:Group 4:204045
203798 | L 3 | 4.36364 | Model Group:Group 4:204045
203799 | L 3 | 4.36364 | Model Group:Group 4:204045
203800 | L 3 | 4.36364 | Model Group:Group 4:204045
203801 | L 3 | 4.36364 | Model Group:Group 4:204045
203802 | L 3 | 4.36364 | Model Group:Group 4:204045
203803 | L 3 | 4.36364 | Model Group:Group 4:204045
203804 | L 3 | 4.25947 | Model Group:Group 4:204045
203805 | L 3 | 4.36364 | Model Group:Group 4:204045
203806 | L 3 | 4.36364 | Model Group:Group 4:204045
203807 | L 3 | 4.36364 | Model Group:Group 4:204045
203808 | L 3 | 4.36364 | Model Group:Group 4:204045
203809 | L 3 | 4.36364 | Model Group:Group 4:204045
203810 | L 3 | 4.36364 | Model Group:Group 4:204045
203811 | L 3 | 4.36364 | Model Group:Group 4:204045
203812 | L 3 | 4.36364 | Model Group:Group 4:204045
203813 | L 3 | 4.36364 | Model Group:Group 4:204045
203814 | L 3 | 7 | Model Group:Group 4:204045
203815 | L 3 | 2 | Model Group:Group 4:204045
203816 | L 3 | 2 | Model Group:Group 4:204045
203817 | L 3 | 7 | Model Group:Group 4:204045
203818 | L 3 | 4.25947 | Model Group:Group 4:204045
203819 | L 3 | 4.36364 | Model Group:Group 4:204045
203820 | L 3 | 4.36364 | Model Group:Group 4:204045
203821 | L 3 | 4.36364 | Model Group:Group 4:204045
203822 | L 3 | 4.36364 | Model Group:Group 4:204045
203823 | L 3 | 4.36364 | Model Group:Group 4:204045
203824 | L 3 | 4.36364 | Model Group:Group 4:204045
203825 | L 3 | 4.36364 | Model Group:Group 4:204045
203826 | L 3 | 4.36364 | Model Group:Group 4:204045
203827 | L 3 | 4.36364 | Model Group:Group 4:204045
203828 | L 3 | 7 | Model Group:Group 4:204045
203829 | L 3 | 7 | Model Group:Group 4:204045
203830 | L 3 | 7 | Model Group:Group 4:204045
203831 | L 3 | 7 | Model Group:Group 4:204045
203832 | L 3 | 7 | Model Group:Group 4:204045
203833 | L 3 | 7 | Model Group:Group 4:204045
203834 | L 3 | 7 | Model Group:Group 4:204045
203835 | L 3 | 7 | Model Group:Group 4:204045
203836 | L 3 | 7 | Model Group:Group 4:204045
203837 | L 3 | 2 | Model Group:Group 4:204045
203838 | L 3 | 2 | Model Group:Group 4:204045
203839 | L 3 | 2 | Model Group:Group 4:204045
203840 | L 3 | 2 | Model Group:Group 4:204045
203841 | L 3 | 2 | Model Group:Group 4:204045
203842 | L 3 | 2 | Model Group:Group 4:204045
203843 | L 3 | 2 | Model Group:Group 4:204045
203844 | L 3 | 2 | Model Group:Group 4:204045
203845 | L 3 | 2 | Model Group:Group 4:204045
203969 | L 3 | 4.36364 | Model Group:Group 4:204045
203970 | L 3 | 4.25947 | Model Group:Group 4:204045
203971 | L 3 | 4.25947 | Model Group:Group 4:204045
203972 | L 3 | 7 | Model Group:Group 4:204045
203973 | L 3 | 2 | Model Group:Group 4:204045
203859 | L 3 | 4.5947 | Model Group:Group 4:204045
203860 | L 3 | 4.5947 | Model Group:Group 4:204045
203861 | L 3 | 4.69886 | Model Group:Group 4:204045
203862 | L 3 | 4.69886 | Model Group:Group 4:204045
203863 | L 3 | 4.5947 | Model Group:Group 4:204045
203864 | L 3 | 4.69886 | Model Group:Group 4:204045
203865 | L 3 | 4.5947 | Model Group:Group 4:204045
203866 | L 3 | 7 | Model Group:Group 4:204045
203867 | L 3 | 2 | Model Group:Group 4:204045
203868 | L 3 | 2 | Model Group:Group 4:204045
203869 | L 3 | 7 | Model Group:Group 4:204045
203870 | L 3 | 4.5947 | Model Group:Group 4:204045
203871 | L 3 | 4.69886 | Model Group:Group 4:204045
203872 | L 3 | 4.69886 | Model Group:Group 4:204045
203873 | L 3 | 4.5947 | Model Group:Group 4:204045
203874 | L 3 | 7 | Model Group:Group 4:204045
203875 | L 3 | 7 | Model Group:Group 4:204045
203876 | L 3 | 7 | Model Group:Group 4:204045
203877 | L 3 | 2 | Model Group:Group 4:204045
203878 | L 3 | 2 | Model Group:Group 4:204045
203879 | L 3 | 2 | Model Group:Group 4:204045
203911 | L 3 | 4.25947 | Model Group:Group 4:204045
203912 | L 3 | 4.25947 | Model Group:Group 4:204045
203913 | L 3 | 4.36364 | Model Group:Group 4:204045
203914 | L 3 | 4.36364 | Model Group:Group 4:204045
203915 | L 3 | 4.36364 | Model Group:Group 4:204045
203916 | L 3 | 4.36364 | Model Group:Group 4:204045
203917 | L 3 | 4.36364 | Model Group:Group 4:204045
203918 | L 3 | 4.36364 | Model Group:Group 4:204045
203919 | L 3 | 4.36364 | Model Group:Group 4:204045
203920 | L 3 | 4.36364 | Model Group:Group 4:204045
203921 | L 3 | 4.25947 | Model Group:Group 4:204045
203922 | L 3 | 4.36364 | Model Group:Group 4:204045
203923 | L 3 | 4.36364 | Model Group:Group 4:204045
203924 | L 3 | 4.36364 | Model Group:Group 4:204045
203925 | L 3 | 4.36364 | Model Group:Group 4:204045
203926 | L 3 | 4.36364 | Model Group:Group 4:204045
203927 | L 3 | 4.36364 | Model Group:Group 4:204045
203928 | L 3 | 4.36364 | Model Group:Group 4:204045
203929 | L 3 | 4.36364 | Model Group:Group 4:204045
203930 | L 3 | 4.36364 | Model Group:Group 4:204045
203931 | L 3 | 7 | Model Group:Group 4:204045
203932 | L 3 | 2 | Model Group:Group 4:204045
203933 | L 3 | 2 | Model Group:Group 4:204045
203934 | L 3 | 7 | Model Group:Group 4:204045
203935 | L 3 | 4.25947 | Model Group:Group 4:204045
203936 | L 3 | 4.36364 | Model Group:Group 4:204045
203937 | L 3 | 4.36364 | Model Group:Group 4:204045
203938 | L 3 | 4.36364 | Model Group:Group 4:204045
203939 | L 3 | 4.36364 | Model Group:Group 4:204045
203940 | L 3 | 4.36364 | Model Group:Group 4:204045
203941 | L 3 | 4.36364 | Model Group:Group 4:204045
203942 | L 3 | 4.36364 | Model Group:Group 4:204045
203943 | L 3 | 4.36364 | Model Group:Group 4:204045
203944 | L 3 | 4.36364 | Model Group:Group 4:204045
203945 | L 3 | 7 | Model Group:Group 4:204045
203946 | L 3 | 7 | Model Group:Group 4:204045
203947 | L 3 | 7 | Model Group:Group 4:204045
203948 | L 3 | 7 | Model Group:Group 4:204045
203949 | L 3 | 7 | Model Group:Group 4:204045
203950 | L 3 | 7 | Model Group:Group 4:204045
203951 | L 3 | 7 | Model Group:Group 4:204045
203952 | L 3 | 7 | Model Group:Group 4:204045
203953 | L 3 | 7 | Model Group:Group 4:204045
203954 | L 3 | 2 | Model Group:Group 4:204045
203955 | L 3 | 2 | Model Group:Group 4:204045
203956 | L 3 | 2 | Model Group:Group 4:204045
203957 | L 3 | 2 | Model Group:Group 4:204045
203958 | L 3 | 2 | Model Group:Group 4:204045
203959 | L 3 | 2 | Model Group:Group 4:204045
203960 | L 3 | 2 | Model Group:Group 4:204045
203961 | L 3 | 2 | Model Group:Group 4:204045
203962 | L 3 | 2 | Model Group:Group 4:204045
203974 | L 3 | 4.36364 | Model Group:Group 4:204045
203975 | L 3 | 4.25947 | Model Group:Group 4:204045
203976 | L 3 | 4.25947 | Model Group:Group 4:204045
203977 | L 3 | 7 | Model Group:Group 4:204045
203978 | L 3 | 2 | Model Group:Group 4:204045
203998 | L 3 | 4.5947 | Model Group:Group 4:204045
203999 | L 3 | 4.5947 | Model Group:Group 4:204045
204000 | L 3 | 4.69886 | Model Group:Group 4:204045
204001 | L 3 | 4.69886 | Model Group:Group 4:204045
204002 | L 3 | 4.5947 | Model Group:Group 4:204045
204003 | L 3 | 4.69886 | Model Group:Group 4:204045
204004 | L 3 | 4.5947 | Model Group:Group 4:204045
204005 | L 3 | 7 | Model Group:Group 4:204045
204006 | L 3 | 2 | Model Group:Group 4:204045
204007 | L 3 | 2 | Model Group:Group 4:204045
204008 | L 3 | 7 | Model Group:Group 4:204045
204009 | L 3 | 4.5947 | Model Group:Group 4:204045
204010 | L 3 | 4.69886 | Model Group:Group 4:204045
204011 | L 3 | 4.69886 | Model Group:Group 4:204045
204012 | L 3 | 4.5947 | Model Group:Group 4:204045
204013 | L 3 | 7 | Model Group:Group 4:204045
204014 | L 3 | 7 | Model Group:Group 4:204045
204015 | L 3 | 7 | Model Group:Group 4:204045
204016 | L 3 | 2 | Model Group:Group 4:204045
204017 | L 3 | 2 | Model Group:Group 4:204045
204018 | L 3 | 2 | Model Group:Group 4:204045
204029 | L 3 | 4.49053 | Model Group:Group 4:204045
204030 | L 3 | 4.49053 | Model Group:Group 4:204045
204031 | L 3 | 4.5947 | Model Group:Group 4:204045
204032 | L 3 | 4.49053 | Model Group:Group 4:204045
204033 | L 3 | 4.49053 | Model Group:Group 4:204045
204034 | L 3 | 7 | Model Group:Group 4:204045
204035 | L 3 | 2 | Model Group:Group 4:204045
204036 | L 3 | 2 | Model Group:Group 4:204045
204037 | L 3 | 7 | Model Group:Group 4:204045
204038 | L 3 | 4.49053 | Model Group:Group 4:204045
204039 | L 3 | 4.5947 | Model Group:Group 4:204045
204040 | L 3 | 4.49053 | Model Group:Group 4:204045
204041 | L 3 | 7 | Model Group:Group 4:204045
204042 | L 3 | 7 | Model Group:Group 4:204045
204043 | L 3 | 2 | Model Group:Group 4:204045
204044 | L 3 | 2 | Model Group:Group 4:204045
204408 | L 5 | 4.6875 | Model Group:Group 4:204782
204409 | L 5 | 4.6875 | Model Group:Group 4:204782
204410 | L 5 | 4.79167 | Model Group:Group 4:204782
204411 | L 5 | 4.6875 | Model Group:Group 4:204782
204412 | L 5 | 7 | Model Group:Group 4:204782
204413 | L 5 | 2 | Model Group:Group 4:204782
204414 | L 5 | 2 | Model Group:Group 4:204782
204415 | L 5 | 7 | Model Group:Group 4:204782
204416 | L 5 | 4.6875 | Model Group:Group 4:204782
204417 | L 5 | 4.79167 | Model Group:Group 4:204782
204418 | L 5 | 4.6875 | Model Group:Group 4:204782
204419 | L 5 | 7 | Model Group:Group 4:204782
204420 | L 5 | 7 | Model Group:Group 4:204782
204421 | L 5 | 2 | Model Group:Group 4:204782
204422 | L 5 | 2 | Model Group:Group 4:204782
204813 | L 5 | 4.79167 | Model Group:Group 4:204782
204433 | L 5 | 4.6875 | Model Group:Group 4:204782
204434 | L 5 | 4.6875 | Model Group:Group 4:204782
204435 | L 5 | 4.79167 | Model Group:Group 4:204782
204436 | L 5 | 4.6875 | Model Group:Group 4:204782
204437 | L 5 | 7 | Model Group:Group 4:204782
204438 | L 5 | 2 | Model Group:Group 4:204782
204439 | L 5 | 2 | Model Group:Group 4:204782
204440 | L 5 | 7 | Model Group:Group 4:204782
204441 | L 5 | 4.6875 | Model Group:Group 4:204782
204442 | L 5 | 4.79167 | Model Group:Group 4:204782
204443 | L 5 | 4.6875 | Model Group:Group 4:204782
204444 | L 5 | 7 | Model Group:Group 4:204782
204445 | L 5 | 7 | Model Group:Group 4:204782
204446 | L 5 | 2 | Model Group:Group 4:204782
204447 | L 5 | 2 | Model Group:Group 4:204782
204812 | L 5 | 4.79167 | Model Group:Group 4:204782
204452 | L 5 | 0.604167 | Model Group:Group 4:204782
204453 | L 5 | 0.604167 | Model Group:Group 4:204782
204454 | L 5 | 7 | Model Group:Group 4:204782
204455 | L 5 | 2 | Model Group:Group 4:204782
204456 | L 5 | 2 | Model Group:Group 4:204782
204457 | L 5 | 7 | Model Group:Group 4:204782
204458 | L 5 | 0.604167 | Model Group:Group 4:204782
204462 | L 5 | 0.604167 | Model Group:Group 4:204782
204463 | L 5 | 2.79167 | Model Group:Group 4:204782
204464 | L 5 | 7 | Model Group:Group 4:204782
204465 | L 5 | 2 | Model Group:Group 4:204782
204469 | L 5 | 2.79167 | Model Group:Group 4:204782
204470 | L 5 | 0.604167 | Model Group:Group 4:204782
204471 | L 5 | 0.604167 | Model Group:Group 4:204782
204472 | L 5 | 7 | Model Group:Group 4:204782
204473 | L 5 | 2 | Model Group:Group 4:204782
204478 | L 5 | 0.604167 | Model Group:Group 4:204782
204479 | L 5 | 0.604167 | Model Group:Group 4:204782
204480 | L 5 | 7 | Model Group:Group 4:204782
204481 | L 5 | 2 | Model Group:Group 4:204782
204482 | L 5 | 2 | Model Group:Group 4:204782
204483 | L 5 | 7 | Model Group:Group 4:204782
204484 | L 5 | 0.604167 | Model Group:Group 4:204782
204488 | L 5 | 0.604167 | Model Group:Group 4:204782
204489 | L 5 | 2.79167 | Model Group:Group 4:204782
204490 | L 5 | 7 | Model Group:Group 4:204782
204491 | L 5 | 2 | Model Group:Group 4:204782
204495 | L 5 | 2.79167 | Model Group:Group 4:204782
204496 | L 5 | 0.604167 | Model Group:Group 4:204782
204497 | L 5 | 0.604167 | Model Group:Group 4:204782
204498 | L 5 | 7 | Model Group:Group 4:204782
204499 | L 5 | 2 | Model Group:Group 4:204782
204531 | L 5 | 4.25947 | Model Group:Group 4:204782
204532 | L 5 | 4.25947 | Model Group:Group 4:204782
204533 | L 5 | 4.36364 | Model Group:Group 4:204782
204534 | L 5 | 4.36364 | Model Group:Group 4:204782
204535 | L 5 | 4.36364 | Model Group:Group 4:204782
204536 | L 5 | 4.36364 | Model Group:Group 4:204782
204537 | L 5 | 4.36364 | Model Group:Group 4:204782
204538 | L 5 | 4.36364 | Model Group:Group 4:204782
204539 | L 5 | 4.36364 | Model Group:Group 4:204782
204540 | L 5 | 4.36364 | Model Group:Group 4:204782
204541 | L 5 | 4.25947 | Model Group:Group 4:204782
204542 | L 5 | 4.36364 | Model Group:Group 4:204782
204543 | L 5 | 4.36364 | Model Group:Group 4:204782
204544 | L 5 | 4.36364 | Model Group:Group 4:204782
204545 | L 5 | 4.36364 | Model Group:Group 4:204782
204546 | L 5 | 4.36364 | Model Group:Group 4:204782
204547 | L 5 | 4.36364 | Model Group:Group 4:204782
204548 | L 5 | 4.36364 | Model Group:Group 4:204782
204549 | L 5 | 4.36364 | Model Group:Group 4:204782
204550 | L 5 | 4.36364 | Model Group:Group 4:204782
204551 | L 5 | 7 | Model Group:Group 4:204782
204552 | L 5 | 2 | Model Group:Group 4:204782
204553 | L 5 | 2 | Model Group:Group 4:204782
204554 | L 5 | 7 | Model Group:Group 4:204782
204555 | L 5 | 4.25947 | Model Group:Group 4:204782
204556 | L 5 | 4.36364 | Model Group:Group 4:204782
204557 | L 5 | 4.36364 | Model Group:Group 4:204782
204558 | L 5 | 4.36364 | Model Group:Group 4:204782
204559 | L 5 | 4.36364 | Model Group:Group 4:204782
204560 | L 5 | 4.36364 | Model Group:Group 4:204782
204561 | L 5 | 4.36364 | Model Group:Group 4:204782
204562 | L 5 | 4.36364 | Model Group:Group 4:204782
204563 | L 5 | 4.36364 | Model Group:Group 4:204782
204564 | L 5 | 4.36364 | Model Group:Group 4:204782
204565 | L 5 | 7 | Model Group:Group 4:204782
204566 | L 5 | 7 | Model Group:Group 4:204782
204567 | L 5 | 7 | Model Group:Group 4:204782
204568 | L 5 | 7 | Model Group:Group 4:204782
204569 | L 5 | 7 | Model Group:Group 4:204782
204570 | L 5 | 7 | Model Group:Group 4:204782
204571 | L 5 | 7 | Model Group:Group 4:204782
204572 | L 5 | 7 | Model Group:Group 4:204782
204573 | L 5 | 7 | Model Group:Group 4:204782
204574 | L 5 | 2 | Model Group:Group 4:204782
204575 | L 5 | 2 | Model Group:Group 4:204782
204576 | L 5 | 2 | Model Group:Group 4:204782
204577 | L 5 | 2 | Model Group:Group 4:204782
204578 | L 5 | 2 | Model Group:Group 4:204782
204579 | L 5 | 2 | Model Group:Group 4:204782
204580 | L 5 | 2 | Model Group:Group 4:204782
204581 | L 5 | 2 | Model Group:Group 4:204782
204582 | L 5 | 2 | Model Group:Group 4:204782
204706 | L 5 | 4.36364 | Model Group:Group 4:204782
204707 | L 5 | 4.25947 | Model Group:Group 4:204782
204708 | L 5 | 4.25947 | Model Group:Group 4:204782
204709 | L 5 | 7 | Model Group:Group 4:204782
204710 | L 5 | 2 | Model Group:Group 4:204782
204596 | L 5 | 4.5947 | Model Group:Group 4:204782
204597 | L 5 | 4.5947 | Model Group:Group 4:204782
204598 | L 5 | 4.69886 | Model Group:Group 4:204782
204599 | L 5 | 4.69886 | Model Group:Group 4:204782
204600 | L 5 | 4.5947 | Model Group:Group 4:204782
204601 | L 5 | 4.69886 | Model Group:Group 4:204782
204602 | L 5 | 4.5947 | Model Group:Group 4:204782
204603 | L 5 | 7 | Model Group:Group 4:204782
204604 | L 5 | 2 | Model Group:Group 4:204782
204605 | L 5 | 2 | Model Group:Group 4:204782
204606 | L 5 | 7 | Model Group:Group 4:204782
204607 | L 5 | 4.5947 | Model Group:Group 4:204782
204608 | L 5 | 4.69886 | Model Group:Group 4:204782
204609 | L 5 | 4.69886 | Model Group:Group 4:204782
204610 | L 5 | 4.5947 | Model Group:Group 4:204782
204611 | L 5 | 7 | Model Group:Group 4:204782
204612 | L 5 | 7 | Model Group:Group 4:204782
204613 | L 5 | 7 | Model Group:Group 4:204782
204614 | L 5 | 2 | Model Group:Group 4:204782
204615 | L 5 | 2 | Model Group:Group 4:204782
204616 | L 5 | 2 | Model Group:Group 4:204782
204648 | L 5 | 4.25947 | Model Group:Group 4:204782
204649 | L 5 | 4.25947 | Model Group:Group 4:204782
204650 | L 5 | 4.36364 | Model Group:Group 4:204782
204651 | L 5 | 4.36364 | Model Group:Group 4:204782
204652 | L 5 | 4.36364 | Model Group:Group 4:204782
204653 | L 5 | 4.36364 | Model Group:Group 4:204782
204654 | L 5 | 4.36364 | Model Group:Group 4:204782
204655 | L 5 | 4.36364 | Model Group:Group 4:204782
204656 | L 5 | 4.36364 | Model Group:Group 4:204782
204657 | L 5 | 4.36364 | Model Group:Group 4:204782
204658 | L 5 | 4.25947 | Model Group:Group 4:204782
204659 | L 5 | 4.36364 | Model Group:Group 4:204782
204660 | L 5 | 4.36364 | Model Group:Group 4:204782
204661 | L 5 | 4.36364 | Model Group:Group 4:204782
204662 | L 5 | 4.36364 | Model Group:Group 4:204782
204663 | L 5 | 4.36364 | Model Group:Group 4:204782
204664 | L 5 | 4.36364 | Model Group:Group 4:204782
204665 | L 5 | 4.36364 | Model Group:Group 4:204782
204666 | L 5 | 4.36364 | Model Group:Group 4:204782
204667 | L 5 | 4.36364 | Model Group:Group 4:204782
204668 | L 5 | 7 | Model Group:Group 4:204782
204669 | L 5 | 2 | Model Group:Group 4:204782
204670 | L 5 | 2 | Model Group:Group 4:204782
204671 | L 5 | 7 | Model Group:Group 4:204782
204672 | L 5 | 4.25947 | Model Group:Group 4:204782
204673 | L 5 | 4.36364 | Model Group:Group 4:204782
204674 | L 5 | 4.36364 | Model Group:Group 4:204782
204675 | L 5 | 4.36364 | Model Group:Group 4:204782
204676 | L 5 | 4.36364 | Model Group:Group 4:204782
204677 | L 5 | 4.36364 | Model Group:Group 4:204782
204678 | L 5 | 4.36364 | Model Group:Group 4:204782
204679 | L 5 | 4.36364 | Model Group:Group 4:204782
204680 | L 5 | 4.36364 | Model Group:Group 4:204782
204681 | L 5 | 4.36364 | Model Group:Group 4:204782
204682 | L 5 | 7 | Model Group:Group 4:204782
204683 | L 5 | 7 | Model Group:Group 4:204782
204684 | L 5 | 7 | Model Group:Group 4:204782
204685 | L 5 | 7 | Model Group:Group 4:204782
204686 | L 5 | 7 | Model Group:Group 4:204782
204687 | L 5 | 7 | Model Group:Group 4:204782
204688 | L 5 | 7 | Model Group:Group 4:204782
204689 | L 5 | 7 | Model Group:Group 4:204782
204690 | L 5 | 7 | Model Group:Group 4:204782
204691 | L 5 | 2 | Model Group:Group 4:204782
204692 | L 5 | 2 | Model Group:Group 4:204782
204693 | L 5 | 2 | Model Group:Group 4:204782
204694 | L 5 | 2 | Model Group:Group 4:204782
204695 | L 5 | 2 | Model Group:Group 4:204782
204696 | L 5 | 2 | Model Group:Group 4:204782
204697 | L 5 | 2 | Model Group:Group 4:204782
204698 | L 5 | 2 | Model Group:Group 4:204782
204699 | L 5 | 2 | Model Group:Group 4:204782
204711 | L 5 | 4.36364 | Model Group:Group 4:204782
204712 | L 5 | 4.25947 | Model Group:Group 4:204782
204713 | L 5 | 4.25947 | Model Group:Group 4:204782
204714 | L 5 | 7 | Model Group:Group 4:204782
204715 | L 5 | 2 | Model Group:Group 4:204782
204735 | L 5 | 4.5947 | Model Group:Group 4:204782
204736 | L 5 | 4.5947 | Model Group:Group 4:204782
204737 | L 5 | 4.69886 | Model Group:Group 4:204782
204738 | L 5 | 4.69886 | Model Group:Group 4:204782
204739 | L 5 | 4.5947 | Model Group:Group 4:204782
204740 | L 5 | 4.69886 | Model Group:Group 4:204782
204741 | L 5 | 4.5947 | Model Group:Group 4:204782
204742 | L 5 | 7 | Model Group:Group 4:204782
204743 | L 5 | 2 | Model Group:Group 4:204782
204744 | L 5 | 2 | Model Group:Group 4:204782
204745 | L 5 | 7 | Model Group:Group 4:204782
204746 | L 5 | 4.5947 | Model Group:Group 4:204782
204747 | L 5 | 4.69886 | Model Group:Group 4:204782
204748 | L 5 | 4.69886 | Model Group:Group 4:204782
204749 | L 5 | 4.5947 | Model Group:Group 4:204782
204750 | L 5 | 7 | Model Group:Group 4:204782
204751 | L 5 | 7 | Model Group:Group 4:204782
204752 | L 5 | 7 | Model Group:Group 4:204782
204753 | L 5 | 2 | Model Group:Group 4:204782
204754 | L 5 | 2 | Model Group:Group 4:204782
204755 | L 5 | 2 | Model Group:Group 4:204782
204766 | L 5 | 4.49053 | Model Group:Group 4:204782
204767 | L 5 | 4.49053 | Model Group:Group 4:204782
204768 | L 5 | 4.5947 | Model Group:Group 4:204782
204769 | L 5 | 4.49053 | Model Group:Group 4:204782
204770 | L 5 | 4.49053 | Model Group:Group 4:204782
204771 | L 5 | 7 | Model Group:Group 4:204782
204772 | L 5 | 2 | Model Group:Group 4:204782
204773 | L 5 | 2 | Model Group:Group 4:204782
204774 | L 5 | 7 | Model Group:Group 4:204782
204775 | L 5 | 4.49053 | Model Group:Group 4:204782
204776 | L 5 | 4.5947 | Model Group:Group 4:204782
204777 | L 5 | 4.49053 | Model Group:Group 4:204782
204778 | L 5 | 7 | Model Group:Group 4:204782
204779 | L 5 | 7 | Model Group:Group 4:204782
204780 | L 5 | 2 | Model Group:Group 4:204782
204781 | L 5 | 2 | Model Group:Group 4:204782
204866 | L 7 | 4.6875 | Model Group:Group 4:205240
204867 | L 7 | 4.6875 | Model Group:Group 4:205240
204868 | L 7 | 4.79167 | Model Group:Group 4:205240
204869 | L 7 | 4.6875 | Model Group:Group 4:205240
204870 | L 7 | 7 | Model Group:Group 4:205240
204871 | L 7 | 2 | Model Group:Group 4:205240
204872 | L 7 | 2 | Model Group:Group 4:205240
204873 | L 7 | 7 | Model Group:Group 4:205240
204874 | L 7 | 4.6875 | Model Group:Group 4:205240
204875 | L 7 | 4.79167 | Model Group:Group 4:205240
204876 | L 7 | 4.6875 | Model Group:Group 4:205240
204877 | L 7 | 7 | Model Group:Group 4:205240
204878 | L 7 | 7 | Model Group:Group 4:205240
204879 | L 7 | 2 | Model Group:Group 4:205240
204880 | L 7 | 2 | Model Group:Group 4:205240
205271 | L 7 | 4.79167 | Model Group:Group 4:205240
204891 | L 7 | 4.6875 | Model Group:Group 4:205240
204892 | L 7 | 4.6875 | Model Group:Group 4:205240
204893 | L 7 | 4.79167 | Model Group:Group 4:205240
204894 | L 7 | 4.6875 | Model Group:Group 4:205240
204895 | L 7 | 7 | Model Group:Group 4:205240
204896 | L 7 | 2 | Model Group:Group 4:205240
204897 | L 7 | 2 | Model Group:Group 4:205240
204898 | L 7 | 7 | Model Group:Group 4:205240
204899 | L 7 | 4.6875 | Model Group:Group 4:205240
204900 | L 7 | 4.79167 | Model Group:Group 4:205240
204901 | L 7 | 4.6875 | Model Group:Group 4:205240
204902 | L 7 | 7 | Model Group:Group 4:205240
204903 | L 7 | 7 | Model Group:Group 4:205240
204904 | L 7 | 2 | Model Group:Group 4:205240
204905 | L 7 | 2 | Model Group:Group 4:205240
205270 | L 7 | 4.79167 | Model Group:Group 4:205240
204910 | L 7 | 0.604167 | Model Group:Group 4:205240
204911 | L 7 | 0.604167 | Model Group:Group 4:205240
204912 | L 7 | 7 | Model Group:Group 4:205240
204913 | L 7 | 2 | Model Group:Group 4:205240
204914 | L 7 | 2 | Model Group:Group 4:205240
204915 | L 7 | 7 | Model Group:Group 4:205240
204916 | L 7 | 0.604167 | Model Group:Group 4:205240
204920 | L 7 | 0.604167 | Model Group:Group 4:205240
204921 | L 7 | 2.79167 | Model Group:Group 4:205240
204922 | L 7 | 7 | Model Group:Group 4:205240
204923 | L 7 | 2 | Model Group:Group 4:205240
204927 | L 7 | 2.79167 | Model Group:Group 4:205240
204928 | L 7 | 0.604167 | Model Group:Group 4:205240
204929 | L 7 | 0.604167 | Model Group:Group 4:205240
204930 | L 7 | 7 | Model Group:Group 4:205240
204931 | L 7 | 2 | Model Group:Group 4:205240
204936 | L 7 | 0.604167 | Model Group:Group 4:205240
204937 | L 7 | 0.604167 | Model Group:Group 4:205240
204938 | L 7 | 7 | Model Group:Group 4:205240
204939 | L 7 | 2 | Model Group:Group 4:205240
204940 | L 7 | 2 | Model Group:Group 4:205240
204941 | L 7 | 7 | Model Group:Group 4:205240
204942 | L 7 | 0.604167 | Model Group:Group 4:205240
204946 | L 7 | 0.604167 | Model Group:Group 4:205240
204947 | L 7 | 2.79167 | Model Group:Group 4:205240
204948 | L 7 | 7 | Model Group:Group 4:205240
204949 | L 7 | 2 | Model Group:Group 4:205240
204953 | L 7 | 2.79167 | Model Group:Group 4:205240
204954 | L 7 | 0.604167 | Model Group:Group 4:205240
204955 | L 7 | 0.604167 | Model Group:Group 4:205240
204956 | L 7 | 7 | Model Group:Group 4:205240
204957 | L 7 | 2 | Model Group:Group 4:205240
204989 | L 7 | 4.25947 | Model Group:Group 4:205240
204990 | L 7 | 4.25947 | Model Group:Group 4:205240
204991 | L 7 | 4.36364 | Model Group:Group 4:205240
204992 | L 7 | 4.36364 | Model Group:Group 4:205240
204993 | L 7 | 4.36364 | Model Group:Group 4:205240
204994 | L 7 | 4.36364 | Model Group:Group 4:205240
204995 | L 7 | 4.36364 | Model Group:Group 4:205240
204996 | L 7 | 4.36364 | Model Group:Group 4:205240
204997 | L 7 | 4.36364 | Model Group:Group 4:205240
204998 | L 7 | 4.36364 | Model Group:Group 4:205240
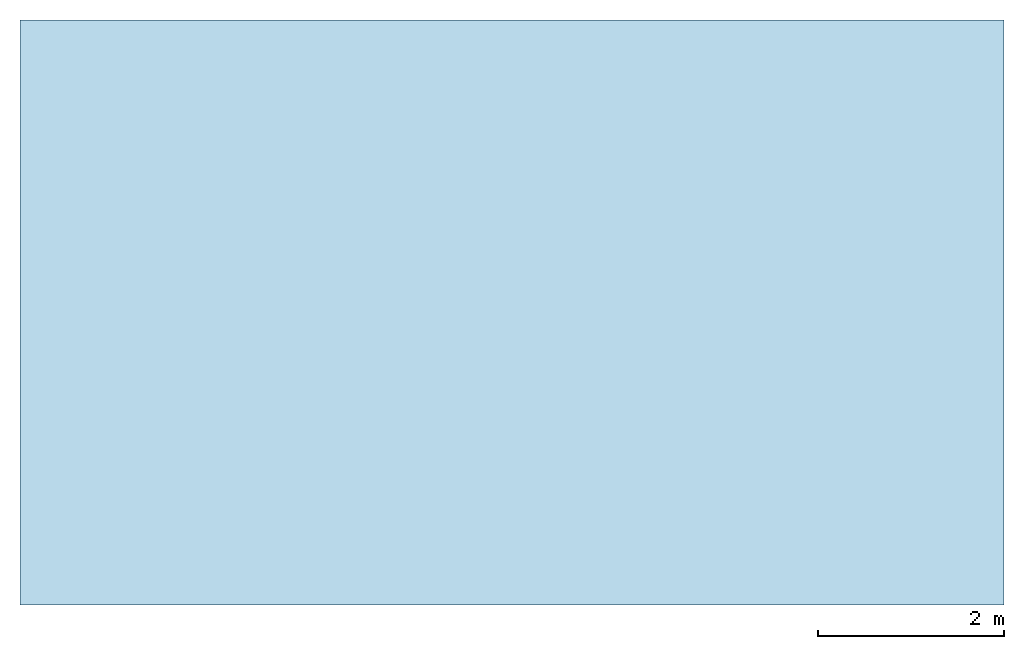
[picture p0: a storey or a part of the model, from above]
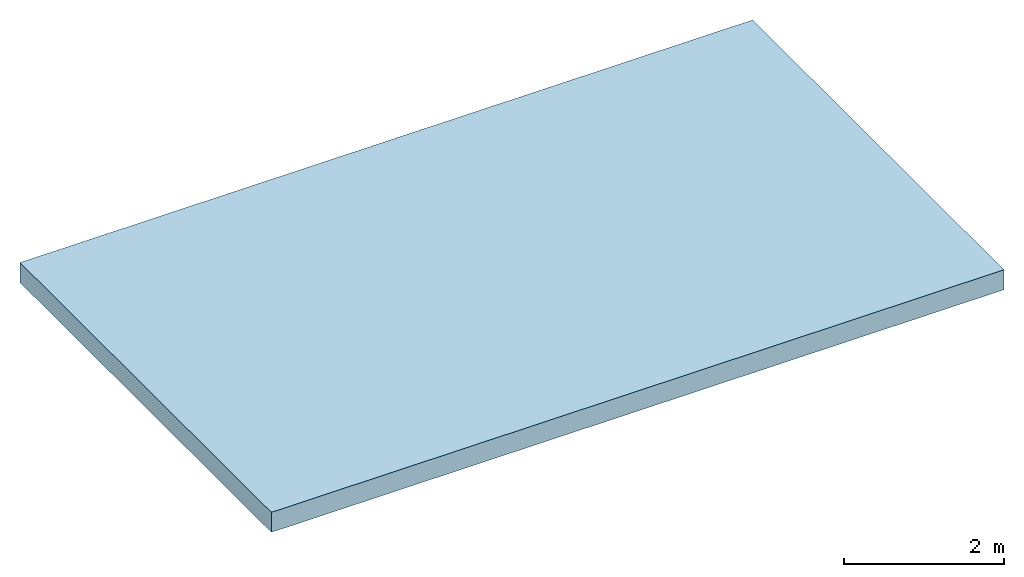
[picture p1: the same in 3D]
Properties of the parts of a building model (IFC2X3), part 2 of 2

# IfcMember: 2.5" x 5" rectangular (1532)
Name (Rectangular Mullion:2.5" x 5" rectangular:...) | In | Span (ft) | Group
204999 | L 7 | 4.25947 | Model Group:Group 4:205240
205000 | L 7 | 4.36364 | Model Group:Group 4:205240
205001 | L 7 | 4.36364 | Model Group:Group 4:205240
205002 | L 7 | 4.36364 | Model Group:Group 4:205240
205003 | L 7 | 4.36364 | Model Group:Group 4:205240
205004 | L 7 | 4.36364 | Model Group:Group 4:205240
205005 | L 7 | 4.36364 | Model Group:Group 4:205240
205006 | L 7 | 4.36364 | Model Group:Group 4:205240
205007 | L 7 | 4.36364 | Model Group:Group 4:205240
205008 | L 7 | 4.36364 | Model Group:Group 4:205240
205009 | L 7 | 7 | Model Group:Group 4:205240
205010 | L 7 | 2 | Model Group:Group 4:205240
205011 | L 7 | 2 | Model Group:Group 4:205240
205012 | L 7 | 7 | Model Group:Group 4:205240
205013 | L 7 | 4.25947 | Model Group:Group 4:205240
205014 | L 7 | 4.36364 | Model Group:Group 4:205240
205015 | L 7 | 4.36364 | Model Group:Group 4:205240
205016 | L 7 | 4.36364 | Model Group:Group 4:205240
205017 | L 7 | 4.36364 | Model Group:Group 4:205240
205018 | L 7 | 4.36364 | Model Group:Group 4:205240
205019 | L 7 | 4.36364 | Model Group:Group 4:205240
205020 | L 7 | 4.36364 | Model Group:Group 4:205240
205021 | L 7 | 4.36364 | Model Group:Group 4:205240
205022 | L 7 | 4.36364 | Model Group:Group 4:205240
205023 | L 7 | 7 | Model Group:Group 4:205240
205024 | L 7 | 7 | Model Group:Group 4:205240
205025 | L 7 | 7 | Model Group:Group 4:205240
205026 | L 7 | 7 | Model Group:Group 4:205240
205027 | L 7 | 7 | Model Group:Group 4:205240
205028 | L 7 | 7 | Model Group:Group 4:205240
205029 | L 7 | 7 | Model Group:Group 4:205240
205030 | L 7 | 7 | Model Group:Group 4:205240
205031 | L 7 | 7 | Model Group:Group 4:205240
205032 | L 7 | 2 | Model Group:Group 4:205240
205033 | L 7 | 2 | Model Group:Group 4:205240
205034 | L 7 | 2 | Model Group:Group 4:205240
205035 | L 7 | 2 | Model Group:Group 4:205240
205036 | L 7 | 2 | Model Group:Group 4:205240
205037 | L 7 | 2 | Model Group:Group 4:205240
205038 | L 7 | 2 | Model Group:Group 4:205240
205039 | L 7 | 2 | Model Group:Group 4:205240
205040 | L 7 | 2 | Model Group:Group 4:205240
205164 | L 7 | 4.36364 | Model Group:Group 4:205240
205165 | L 7 | 4.25947 | Model Group:Group 4:205240
205166 | L 7 | 4.25947 | Model Group:Group 4:205240
205167 | L 7 | 7 | Model Group:Group 4:205240
205168 | L 7 | 2 | Model Group:Group 4:205240
205054 | L 7 | 4.5947 | Model Group:Group 4:205240
205055 | L 7 | 4.5947 | Model Group:Group 4:205240
205056 | L 7 | 4.69886 | Model Group:Group 4:205240
205057 | L 7 | 4.69886 | Model Group:Group 4:205240
205058 | L 7 | 4.5947 | Model Group:Group 4:205240
205059 | L 7 | 4.69886 | Model Group:Group 4:205240
205060 | L 7 | 4.5947 | Model Group:Group 4:205240
205061 | L 7 | 7 | Model Group:Group 4:205240
205062 | L 7 | 2 | Model Group:Group 4:205240
205063 | L 7 | 2 | Model Group:Group 4:205240
205064 | L 7 | 7 | Model Group:Group 4:205240
205065 | L 7 | 4.5947 | Model Group:Group 4:205240
205066 | L 7 | 4.69886 | Model Group:Group 4:205240
205067 | L 7 | 4.69886 | Model Group:Group 4:205240
205068 | L 7 | 4.5947 | Model Group:Group 4:205240
205069 | L 7 | 7 | Model Group:Group 4:205240
205070 | L 7 | 7 | Model Group:Group 4:205240
205071 | L 7 | 7 | Model Group:Group 4:205240
205072 | L 7 | 2 | Model Group:Group 4:205240
205073 | L 7 | 2 | Model Group:Group 4:205240
205074 | L 7 | 2 | Model Group:Group 4:205240
205106 | L 7 | 4.25947 | Model Group:Group 4:205240
205107 | L 7 | 4.25947 | Model Group:Group 4:205240
205108 | L 7 | 4.36364 | Model Group:Group 4:205240
205109 | L 7 | 4.36364 | Model Group:Group 4:205240
205110 | L 7 | 4.36364 | Model Group:Group 4:205240
205111 | L 7 | 4.36364 | Model Group:Group 4:205240
205112 | L 7 | 4.36364 | Model Group:Group 4:205240
205113 | L 7 | 4.36364 | Model Group:Group 4:205240
205114 | L 7 | 4.36364 | Model Group:Group 4:205240
205115 | L 7 | 4.36364 | Model Group:Group 4:205240
205116 | L 7 | 4.25947 | Model Group:Group 4:205240
205117 | L 7 | 4.36364 | Model Group:Group 4:205240
205118 | L 7 | 4.36364 | Model Group:Group 4:205240
205119 | L 7 | 4.36364 | Model Group:Group 4:205240
205120 | L 7 | 4.36364 | Model Group:Group 4:205240
205121 | L 7 | 4.36364 | Model Group:Group 4:205240
205122 | L 7 | 4.36364 | Model Group:Group 4:205240
205123 | L 7 | 4.36364 | Model Group:Group 4:205240
205124 | L 7 | 4.36364 | Model Group:Group 4:205240
205125 | L 7 | 4.36364 | Model Group:Group 4:205240
205126 | L 7 | 7 | Model Group:Group 4:205240
205127 | L 7 | 2 | Model Group:Group 4:205240
205128 | L 7 | 2 | Model Group:Group 4:205240
205129 | L 7 | 7 | Model Group:Group 4:205240
205130 | L 7 | 4.25947 | Model Group:Group 4:205240
205131 | L 7 | 4.36364 | Model Group:Group 4:205240
205132 | L 7 | 4.36364 | Model Group:Group 4:205240
205133 | L 7 | 4.36364 | Model Group:Group 4:205240
205134 | L 7 | 4.36364 | Model Group:Group 4:205240
205135 | L 7 | 4.36364 | Model Group:Group 4:205240
205136 | L 7 | 4.36364 | Model Group:Group 4:205240
205137 | L 7 | 4.36364 | Model Group:Group 4:205240
205138 | L 7 | 4.36364 | Model Group:Group 4:205240
205139 | L 7 | 4.36364 | Model Group:Group 4:205240
205140 | L 7 | 7 | Model Group:Group 4:205240
205141 | L 7 | 7 | Model Group:Group 4:205240
205142 | L 7 | 7 | Model Group:Group 4:205240
205143 | L 7 | 7 | Model Group:Group 4:205240
205144 | L 7 | 7 | Model Group:Group 4:205240
205145 | L 7 | 7 | Model Group:Group 4:205240
205146 | L 7 | 7 | Model Group:Group 4:205240
205147 | L 7 | 7 | Model Group:Group 4:205240
205148 | L 7 | 7 | Model Group:Group 4:205240
205149 | L 7 | 2 | Model Group:Group 4:205240
205150 | L 7 | 2 | Model Group:Group 4:205240
205151 | L 7 | 2 | Model Group:Group 4:205240
205152 | L 7 | 2 | Model Group:Group 4:205240
205153 | L 7 | 2 | Model Group:Group 4:205240
205154 | L 7 | 2 | Model Group:Group 4:205240
205155 | L 7 | 2 | Model Group:Group 4:205240
205156 | L 7 | 2 | Model Group:Group 4:205240
205157 | L 7 | 2 | Model Group:Group 4:205240
205169 | L 7 | 4.36364 | Model Group:Group 4:205240
205170 | L 7 | 4.25947 | Model Group:Group 4:205240
205171 | L 7 | 4.25947 | Model Group:Group 4:205240
205172 | L 7 | 7 | Model Group:Group 4:205240
205173 | L 7 | 2 | Model Group:Group 4:205240
205193 | L 7 | 4.5947 | Model Group:Group 4:205240
205194 | L 7 | 4.5947 | Model Group:Group 4:205240
205195 | L 7 | 4.69886 | Model Group:Group 4:205240
205196 | L 7 | 4.69886 | Model Group:Group 4:205240
205197 | L 7 | 4.5947 | Model Group:Group 4:205240
205198 | L 7 | 4.69886 | Model Group:Group 4:205240
205199 | L 7 | 4.5947 | Model Group:Group 4:205240
205200 | L 7 | 7 | Model Group:Group 4:205240
205201 | L 7 | 2 | Model Group:Group 4:205240
205202 | L 7 | 2 | Model Group:Group 4:205240
205203 | L 7 | 7 | Model Group:Group 4:205240
205204 | L 7 | 4.5947 | Model Group:Group 4:205240
205205 | L 7 | 4.69886 | Model Group:Group 4:205240
205206 | L 7 | 4.69886 | Model Group:Group 4:205240
205207 | L 7 | 4.5947 | Model Group:Group 4:205240
205208 | L 7 | 7 | Model Group:Group 4:205240
205209 | L 7 | 7 | Model Group:Group 4:205240
205210 | L 7 | 7 | Model Group:Group 4:205240
205211 | L 7 | 2 | Model Group:Group 4:205240
205212 | L 7 | 2 | Model Group:Group 4:205240
205213 | L 7 | 2 | Model Group:Group 4:205240
205224 | L 7 | 4.49053 | Model Group:Group 4:205240
205225 | L 7 | 4.49053 | Model Group:Group 4:205240
205226 | L 7 | 4.5947 | Model Group:Group 4:205240
205227 | L 7 | 4.49053 | Model Group:Group 4:205240
205228 | L 7 | 4.49053 | Model Group:Group 4:205240
205229 | L 7 | 7 | Model Group:Group 4:205240
205230 | L 7 | 2 | Model Group:Group 4:205240
205231 | L 7 | 2 | Model Group:Group 4:205240
205232 | L 7 | 7 | Model Group:Group 4:205240
205233 | L 7 | 4.49053 | Model Group:Group 4:205240
205234 | L 7 | 4.5947 | Model Group:Group 4:205240
205235 | L 7 | 4.49053 | Model Group:Group 4:205240
205236 | L 7 | 7 | Model Group:Group 4:205240
205237 | L 7 | 7 | Model Group:Group 4:205240
205238 | L 7 | 2 | Model Group:Group 4:205240
205239 | L 7 | 2 | Model Group:Group 4:205240
205306 | L 9 | 4.6875
205307 | L 9 | 4.6875
205308 | L 9 | 4.79167
205309 | L 9 | 4.6875
205310 | L 9 | 7
205311 | L 9 | 2
205312 | L 9 | 2
205313 | L 9 | 7
205314 | L 9 | 4.6875
205315 | L 9 | 4.79167
205316 | L 9 | 4.6875
205317 | L 9 | 7
205318 | L 9 | 7
205319 | L 9 | 2
205320 | L 9 | 2
205711 | L 9 | 4.79167
205331 | L 9 | 4.6875
205332 | L 9 | 4.6875
205333 | L 9 | 4.79167
205334 | L 9 | 4.6875
205335 | L 9 | 7
205336 | L 9 | 2
205337 | L 9 | 2
205338 | L 9 | 7
205339 | L 9 | 4.6875
205340 | L 9 | 4.79167
205341 | L 9 | 4.6875
205342 | L 9 | 7
205343 | L 9 | 7
205344 | L 9 | 2
205345 | L 9 | 2
205710 | L 9 | 4.79167
205350 | L 9 | 0.604167 | Model Group:Array Group 2:207312
205351 | L 9 | 0.604167 | Model Group:Array Group 2:207312
205352 | L 9 | 7 | Model Group:Array Group 2:207312
205353 | L 9 | 2 | Model Group:Array Group 2:207312
205354 | L 9 | 2 | Model Group:Array Group 2:207312
205355 | L 9 | 7 | Model Group:Array Group 2:207312
205356 | L 9 | 0.604167 | Model Group:Array Group 2:207312
205360 | L 9 | 0.604167 | Model Group:Array Group 2:207312
205361 | L 9 | 2.79167 | Model Group:Array Group 2:207312
205362 | L 9 | 7 | Model Group:Array Group 2:207312
205363 | L 9 | 2 | Model Group:Array Group 2:207312
205367 | L 9 | 2.79167 | Model Group:Array Group 2:207312
205368 | L 9 | 0.604167 | Model Group:Array Group 2:207312
205369 | L 9 | 0.604167 | Model Group:Array Group 2:207312
205370 | L 9 | 7 | Model Group:Array Group 2:207312
205371 | L 9 | 2 | Model Group:Array Group 2:207312
205376 | L 9 | 0.604167 | Model Group:Array Group 2:207312
205377 | L 9 | 0.604167 | Model Group:Array Group 2:207312
205378 | L 9 | 7 | Model Group:Array Group 2:207312
205379 | L 9 | 2 | Model Group:Array Group 2:207312
205380 | L 9 | 2 | Model Group:Array Group 2:207312
205381 | L 9 | 7 | Model Group:Array Group 2:207312
205382 | L 9 | 0.604167 | Model Group:Array Group 2:207312
205386 | L 9 | 0.604167 | Model Group:Array Group 2:207312
205387 | L 9 | 2.79167 | Model Group:Array Group 2:207312
205388 | L 9 | 7 | Model Group:Array Group 2:207312
205389 | L 9 | 2 | Model Group:Array Group 2:207312
205393 | L 9 | 2.79167 | Model Group:Array Group 2:207312
205394 | L 9 | 0.604167 | Model Group:Array Group 2:207312
205395 | L 9 | 0.604167 | Model Group:Array Group 2:207312
205396 | L 9 | 7 | Model Group:Array Group 2:207312
205397 | L 9 | 2 | Model Group:Array Group 2:207312
205429 | L 9 | 4.25947
205430 | L 9 | 4.25947
205431 | L 9 | 4.36364
205432 | L 9 | 4.36364
205433 | L 9 | 4.36364
205434 | L 9 | 4.36364
205435 | L 9 | 4.36364
205436 | L 9 | 4.36364
205437 | L 9 | 4.36364
205438 | L 9 | 4.36364
205439 | L 9 | 4.25947
205440 | L 9 | 4.36364
205441 | L 9 | 4.36364
205442 | L 9 | 4.36364
205443 | L 9 | 4.36364
205444 | L 9 | 4.36364
205445 | L 9 | 4.36364
205446 | L 9 | 4.36364
205447 | L 9 | 4.36364
205448 | L 9 | 4.36364
205449 | L 9 | 7
205450 | L 9 | 2
205451 | L 9 | 2
205452 | L 9 | 7
205453 | L 9 | 4.25947
205454 | L 9 | 4.36364
205455 | L 9 | 4.36364
205456 | L 9 | 4.36364
205457 | L 9 | 4.36364
205458 | L 9 | 4.36364
205459 | L 9 | 4.36364
205460 | L 9 | 4.36364
205461 | L 9 | 4.36364
205462 | L 9 | 4.36364
205463 | L 9 | 7
205464 | L 9 | 7
205465 | L 9 | 7
205466 | L 9 | 7
205467 | L 9 | 7
205468 | L 9 | 7
205469 | L 9 | 7
205470 | L 9 | 7
205471 | L 9 | 7
205472 | L 9 | 2
205473 | L 9 | 2
205474 | L 9 | 2
205475 | L 9 | 2
205476 | L 9 | 2
205477 | L 9 | 2
205478 | L 9 | 2
205479 | L 9 | 2
205480 | L 9 | 2
205604 | L 9 | 4.36364
205605 | L 9 | 4.25947
205606 | L 9 | 4.25947
205607 | L 9 | 7
205608 | L 9 | 2
205494 | L 9 | 4.5947
205495 | L 9 | 4.5947
205496 | L 9 | 4.69886
205497 | L 9 | 4.69886
205498 | L 9 | 4.5947
205499 | L 9 | 4.69886
205500 | L 9 | 4.5947
205501 | L 9 | 7
205502 | L 9 | 2
205503 | L 9 | 2
205504 | L 9 | 7
205505 | L 9 | 4.5947
205506 | L 9 | 4.69886
205507 | L 9 | 4.69886
205508 | L 9 | 4.5947
205509 | L 9 | 7
205510 | L 9 | 7
205511 | L 9 | 7
205512 | L 9 | 2
205513 | L 9 | 2
205514 | L 9 | 2
205546 | L 9 | 4.25947
205547 | L 9 | 4.25947
205548 | L 9 | 4.36364
205549 | L 9 | 4.36364
205550 | L 9 | 4.36364
205551 | L 9 | 4.36364
205552 | L 9 | 4.36364
205553 | L 9 | 4.36364
205554 | L 9 | 4.36364
205555 | L 9 | 4.36364
205556 | L 9 | 4.25947
205557 | L 9 | 4.36364
205558 | L 9 | 4.36364
205559 | L 9 | 4.36364
205560 | L 9 | 4.36364
205561 | L 9 | 4.36364
205562 | L 9 | 4.36364
205563 | L 9 | 4.36364
205564 | L 9 | 4.36364
205565 | L 9 | 4.36364
205566 | L 9 | 7
205567 | L 9 | 2
205568 | L 9 | 2
205569 | L 9 | 7
205570 | L 9 | 4.25947
205571 | L 9 | 4.36364
205572 | L 9 | 4.36364
205573 | L 9 | 4.36364
205574 | L 9 | 4.36364
205575 | L 9 | 4.36364
205576 | L 9 | 4.36364
205577 | L 9 | 4.36364
205578 | L 9 | 4.36364
205579 | L 9 | 4.36364
205580 | L 9 | 7
205581 | L 9 | 7
205582 | L 9 | 7
205583 | L 9 | 7
205584 | L 9 | 7
205585 | L 9 | 7
205586 | L 9 | 7
205587 | L 9 | 7
205588 | L 9 | 7
205589 | L 9 | 2
205590 | L 9 | 2
205591 | L 9 | 2
205592 | L 9 | 2
205593 | L 9 | 2
205594 | L 9 | 2
205595 | L 9 | 2
205596 | L 9 | 2
205597 | L 9 | 2
205609 | L 9 | 4.36364
205610 | L 9 | 4.25947
205611 | L 9 | 4.25947
205612 | L 9 | 7
205613 | L 9 | 2
205633 | L 9 | 4.5947
205634 | L 9 | 4.5947
205635 | L 9 | 4.69886
205636 | L 9 | 4.69886
205637 | L 9 | 4.5947
205638 | L 9 | 4.69886
205639 | L 9 | 4.5947
205640 | L 9 | 7
205641 | L 9 | 2
205642 | L 9 | 2
205643 | L 9 | 7
205644 | L 9 | 4.5947
205645 | L 9 | 4.69886
205646 | L 9 | 4.69886
205647 | L 9 | 4.5947
205648 | L 9 | 7
205649 | L 9 | 7
205650 | L 9 | 7
205651 | L 9 | 2
205652 | L 9 | 2
205653 | L 9 | 2
205664 | L 9 | 4.49053
205665 | L 9 | 4.49053
205666 | L 9 | 4.5947
205667 | L 9 | 4.49053
205668 | L 9 | 4.49053
205669 | L 9 | 7
205670 | L 9 | 2
205671 | L 9 | 2
205672 | L 9 | 7
205673 | L 9 | 4.49053
205674 | L 9 | 4.5947
205675 | L 9 | 4.49053
205676 | L 9 | 7
205677 | L 9 | 7
205678 | L 9 | 2
205679 | L 9 | 2
207319 | L 11 | 0.604167
207320 | L 11 | 0.604167
207321 | L 11 | 7
207322 | L 11 | 1
207323 | L 11 | 1
207324 | L 11 | 7
207325 | L 11 | 0.604167
207329 | L 11 | 0.604167
207330 | L 11 | 2.79167
207331 | L 11 | 7
207332 | L 11 | 1
207336 | L 11 | 2.79167
207337 | L 11 | 0.604167
207338 | L 11 | 0.604167
207339 | L 11 | 7
207340 | L 11 | 1
207345 | L 11 | 0.604167
207346 | L 11 | 0.604167
207347 | L 11 | 7
207348 | L 11 | 1
207349 | L 11 | 1
207350 | L 11 | 7
207351 | L 11 | 0.604167
207355 | L 11 | 0.604167
207356 | L 11 | 2.79167
207357 | L 11 | 7
207358 | L 11 | 1
207362 | L 11 | 2.79167
207363 | L 11 | 0.604167
207364 | L 11 | 0.604167
207365 | L 11 | 7
207366 | L 11 | 1

# IfcMember: Stringer:Stringer - 2" Width (48)
Type - PredefinedType: STRINGER
Classification: C Interiors (Uniformat)
Pset_MemberCommon - Reference: 7" max riser 11" tread; IsExternal: no; LoadBearing: yes; Span: 0.166667 ft; Slope: 0 deg
Name (Assembled Stair:Stair:...) | In
188699 Stringer 1 | Level 1
188699 Stringer 2 | Level 1
188782 Stringer 1 | Level 1
188782 Stringer 2 | Level 1
189066 Stringer 1 | L 1
189066 Stringer 2 | L 1
189066 Stringer 3 | L 1
189066 Stringer 4 | L 1
189410 Stringer 1 | Level 2
189410 Stringer 2 | Level 2
189410 Stringer 3 | Level 2
189410 Stringer 4 | Level 2
190141 Stringer 1 | L 2
190141 Stringer 2 | L 2
190141 Stringer 3 | L 2
190141 Stringer 4 | L 2
190399 Stringer 1 | L 3
190399 Stringer 2 | L 3
190399 Stringer 3 | L 3
190399 Stringer 4 | L 3
190655 Stringer 1 | L 4
190655 Stringer 2 | L 4
190655 Stringer 3 | L 4
190655 Stringer 4 | L 4
190903 Stringer 1 | L 5
190903 Stringer 2 | L 5
190903 Stringer 3 | L 5
190903 Stringer 4 | L 5
191158 Stringer 1 | L 6
191158 Stringer 2 | L 6
191158 Stringer 3 | L 6
191158 Stringer 4 | L 6
191385 Stringer 1 | L 7
191385 Stringer 2 | L 7
191385 Stringer 3 | L 7
191385 Stringer 4 | L 7
191601 Stringer 1 | L 8
191601 Stringer 2 | L 8
191601 Stringer 3 | L 8
191601 Stringer 4 | L 8
206083 Stringer 1 | L 9
206083 Stringer 2 | L 9
206209 Stringer 1 | L 9
206209 Stringer 2 | L 9
206445 Stringer 1 | L 10
206445 Stringer 2 | L 10
206840 Stringer 1 | L 10
206840 Stringer 2 | L 10

# IfcOpeningElement: Opening (36)
Classification: B2010 Exterior Walls (Uniformat)
Name (Basic Wall:Generic - 6":...) | In | Group
2 x 198686 | Level 1 | Model Group:Group 3:200611
2 x 198800 | Level 1 | Model Group:Group 3:200611
199107 | Level 1 | Model Group:Group 3:200611
199174 | Level 1 | Model Group:Group 3:200611
2 x 201832 | Level 2 | Model Group:Group 4:201905
2 x 201833 | Level 2 | Model Group:Group 4:201905
201836 | Level 2 | Model Group:Group 4:201905
201837 | Level 2 | Model Group:Group 4:201905
2 x 203979 | L 3 | Model Group:Group 4:204045
2 x 203980 | L 3 | Model Group:Group 4:204045
203983 | L 3 | Model Group:Group 4:204045
203984 | L 3 | Model Group:Group 4:204045
2 x 204716 | L 5 | Model Group:Group 4:204782
2 x 204717 | L 5 | Model Group:Group 4:204782
204720 | L 5 | Model Group:Group 4:204782
204721 | L 5 | Model Group:Group 4:204782
2 x 205174 | L 7 | Model Group:Group 4:205240
2 x 205175 | L 7 | Model Group:Group 4:205240
205178 | L 7 | Model Group:Group 4:205240
205179 | L 7 | Model Group:Group 4:205240
2 x 205614 | L 9
2 x 205615 | L 9
205618 | L 9
205619 | L 9

# IfcPlate: Glazed (542)
Type - ElementType: Glazed; PredefinedType: CURTAIN_PANEL; Material: <Unnamed> 0.0833333 ft
Classification: B2020200 Curtain Walls (Uniformat)
Pset_PlateCommon - LoadBearing: yes; IsExternal: yes; Reference: Glazed; ThermalTransmittance: 6.7069 kg/K/s3
Name (System Panel:Glazed:...) | In | Group
194279 | Level 1
194282 | Level 1
194284 | Level 1
194285 | Level 1
194287 | Level 1
194288 | Level 1
194348 | Level 1
194349 | Level 1
194351 | Level 1
194352 | Level 1
194354 | Level 1
194355 | Level 1
194357 | Level 1
194358 | Level 1
194360 | Level 1
194361 | Level 1
194453 | Level 1
194454 | Level 1
194456 | Level 1
194457 | Level 1
194459 | Level 1
194460 | Level 1
194462 | Level 1
194463 | Level 1
206405 | Level 1
206406 | Level 1
206408 | Level 1
206409 | Level 1
196428 | Level 1 | Model Group:Group 3:200611
196434 | Level 1 | Model Group:Group 3:200611
196438 | Level 1 | Model Group:Group 3:200611
196439 | Level 1 | Model Group:Group 3:200611
196440 | Level 1 | Model Group:Group 3:200611
196768 | Level 1 | Model Group:Group 3:200611
196772 | Level 1 | Model Group:Group 3:200611
196774 | Level 1 | Model Group:Group 3:200611
196775 | Level 1 | Model Group:Group 3:200611
196776 | Level 1 | Model Group:Group 3:200611
196929 | Level 1 | Model Group:Group 3:200611
197331 | Level 1 | Model Group:Group 3:200611
196935 | Level 1 | Model Group:Group 3:200611
197199 | Level 1 | Model Group:Group 3:200611
197332 | Level 1 | Model Group:Group 3:200611
197504 | Level 1 | Model Group:Group 3:200611
197522 | Level 1 | Model Group:Group 3:200611
197506 | Level 1 | Model Group:Group 3:200611
197516 | Level 1 | Model Group:Group 3:200611
197523 | Level 1 | Model Group:Group 3:200611
197880 | Level 1 | Model Group:Group 3:200611
197883 | Level 1 | Model Group:Group 3:200611
197885 | Level 1 | Model Group:Group 3:200611
197887 | Level 1 | Model Group:Group 3:200611
197889 | Level 1 | Model Group:Group 3:200611
197891 | Level 1 | Model Group:Group 3:200611
197893 | Level 1 | Model Group:Group 3:200611
197895 | Level 1 | Model Group:Group 3:200611
197897 | Level 1 | Model Group:Group 3:200611
197899 | Level 1 | Model Group:Group 3:200611
198384 | Level 1 | Model Group:Group 3:200611
198459 | Level 1 | Model Group:Group 3:200611
197901 | Level 1 | Model Group:Group 3:200611
197902 | Level 1 | Model Group:Group 3:200611
197903 | Level 1 | Model Group:Group 3:200611
197904 | Level 1 | Model Group:Group 3:200611
197905 | Level 1 | Model Group:Group 3:200611
197906 | Level 1 | Model Group:Group 3:200611
197907 | Level 1 | Model Group:Group 3:200611
197908 | Level 1 | Model Group:Group 3:200611
197909 | Level 1 | Model Group:Group 3:200611
197910 | Level 1 | Model Group:Group 3:200611
198385 | Level 1 | Model Group:Group 3:200611
198460 | Level 1 | Model Group:Group 3:200611
198088 | Level 1 | Model Group:Group 3:200611
198091 | Level 1 | Model Group:Group 3:200611
198093 | Level 1 | Model Group:Group 3:200611
198095 | Level 1 | Model Group:Group 3:200611
198111 | Level 1 | Model Group:Group 3:200611
198112 | Level 1 | Model Group:Group 3:200611
198113 | Level 1 | Model Group:Group 3:200611
198114 | Level 1 | Model Group:Group 3:200611
198261 | Level 1 | Model Group:Group 3:200611
198264 | Level 1 | Model Group:Group 3:200611
198266 | Level 1 | Model Group:Group 3:200611
198268 | Level 1 | Model Group:Group 3:200611
198270 | Level 1 | Model Group:Group 3:200611
198272 | Level 1 | Model Group:Group 3:200611
198274 | Level 1 | Model Group:Group 3:200611
198276 | Level 1 | Model Group:Group 3:200611
198278 | Level 1 | Model Group:Group 3:200611
198280 | Level 1 | Model Group:Group 3:200611
198387 | Level 1 | Model Group:Group 3:200611
198462 | Level 1 | Model Group:Group 3:200611
198282 | Level 1 | Model Group:Group 3:200611
198283 | Level 1 | Model Group:Group 3:200611
198284 | Level 1 | Model Group:Group 3:200611
198285 | Level 1 | Model Group:Group 3:200611
198286 | Level 1 | Model Group:Group 3:200611
198287 | Level 1 | Model Group:Group 3:200611
198288 | Level 1 | Model Group:Group 3:200611
198289 | Level 1 | Model Group:Group 3:200611
198290 | Level 1 | Model Group:Group 3:200611
198291 | Level 1 | Model Group:Group 3:200611
198388 | Level 1 | Model Group:Group 3:200611
198463 | Level 1 | Model Group:Group 3:200611
200149 | Level 1 | Model Group:Group 3:200611
200151 | Level 1 | Model Group:Group 3:200611
200153 | Level 1 | Model Group:Group 3:200611
200155 | Level 1 | Model Group:Group 3:200611
200157 | Level 1 | Model Group:Group 3:200611
200158 | Level 1 | Model Group:Group 3:200611
200159 | Level 1 | Model Group:Group 3:200611
200160 | Level 1 | Model Group:Group 3:200611
200337 | Level 1 | Model Group:Group 3:200611
200344 | Level 1 | Model Group:Group 3:200611
200346 | Level 1 | Model Group:Group 3:200611
200347 | Level 1 | Model Group:Group 3:200611
200348 | Level 1 | Model Group:Group 3:200611
201498 | Level 2 | Model Group:Group 4:201905
201500 | Level 2 | Model Group:Group 4:201905
201502 | Level 2 | Model Group:Group 4:201905
201503 | Level 2 | Model Group:Group 4:201905
201504 | Level 2 | Model Group:Group 4:201905
201522 | Level 2 | Model Group:Group 4:201905
201524 | Level 2 | Model Group:Group 4:201905
201528 | Level 2 | Model Group:Group 4:201905
201529 | Level 2 | Model Group:Group 4:201905
201530 | Level 2 | Model Group:Group 4:201905
201548 | Level 2 | Model Group:Group 4:201905
201566 | Level 2 | Model Group:Group 4:201905
201550 | Level 2 | Model Group:Group 4:201905
201560 | Level 2 | Model Group:Group 4:201905
201567 | Level 2 | Model Group:Group 4:201905
201574 | Level 2 | Model Group:Group 4:201905
201592 | Level 2 | Model Group:Group 4:201905
201576 | Level 2 | Model Group:Group 4:201905
201586 | Level 2 | Model Group:Group 4:201905
201593 | Level 2 | Model Group:Group 4:201905
201600 | Level 2 | Model Group:Group 4:201905
201602 | Level 2 | Model Group:Group 4:201905
201604 | Level 2 | Model Group:Group 4:201905
201606 | Level 2 | Model Group:Group 4:201905
201608 | Level 2 | Model Group:Group 4:201905
201610 | Level 2 | Model Group:Group 4:201905
201612 | Level 2 | Model Group:Group 4:201905
201614 | Level 2 | Model Group:Group 4:201905
201616 | Level 2 | Model Group:Group 4:201905
201618 | Level 2 | Model Group:Group 4:201905
201801 | Level 2 | Model Group:Group 4:201905
201620 | Level 2 | Model Group:Group 4:201905
201621 | Level 2 | Model Group:Group 4:201905
201622 | Level 2 | Model Group:Group 4:201905
201623 | Level 2 | Model Group:Group 4:201905
201624 | Level 2 | Model Group:Group 4:201905
201625 | Level 2 | Model Group:Group 4:201905
201626 | Level 2 | Model Group:Group 4:201905
201627 | Level 2 | Model Group:Group 4:201905
201628 | Level 2 | Model Group:Group 4:201905
201629 | Level 2 | Model Group:Group 4:201905
201802 | Level 2 | Model Group:Group 4:201905
201683 | Level 2 | Model Group:Group 4:201905
201687 | Level 2 | Model Group:Group 4:201905
201689 | Level 2 | Model Group:Group 4:201905
201691 | Level 2 | Model Group:Group 4:201905
201692 | Level 2 | Model Group:Group 4:201905
201693 | Level 2 | Model Group:Group 4:201905
201694 | Level 2 | Model Group:Group 4:201905
201718 | Level 2 | Model Group:Group 4:201905
201720 | Level 2 | Model Group:Group 4:201905
201722 | Level 2 | Model Group:Group 4:201905
201724 | Level 2 | Model Group:Group 4:201905
201726 | Level 2 | Model Group:Group 4:201905
201728 | Level 2 | Model Group:Group 4:201905
201730 | Level 2 | Model Group:Group 4:201905
201732 | Level 2 | Model Group:Group 4:201905
201734 | Level 2 | Model Group:Group 4:201905
201736 | Level 2 | Model Group:Group 4:201905
201804 | Level 2 | Model Group:Group 4:201905
201738 | Level 2 | Model Group:Group 4:201905
201739 | Level 2 | Model Group:Group 4:201905
201740 | Level 2 | Model Group:Group 4:201905
201741 | Level 2 | Model Group:Group 4:201905
201742 | Level 2 | Model Group:Group 4:201905
201743 | Level 2 | Model Group:Group 4:201905
201744 | Level 2 | Model Group:Group 4:201905
201745 | Level 2 | Model Group:Group 4:201905
201746 | Level 2 | Model Group:Group 4:201905
201747 | Level 2 | Model Group:Group 4:201905
201805 | Level 2 | Model Group:Group 4:201905
201845 | Level 2 | Model Group:Group 4:201905
201847 | Level 2 | Model Group:Group 4:201905
201851 | Level 2 | Model Group:Group 4:201905
201853 | Level 2 | Model Group:Group 4:201905
201854 | Level 2 | Model Group:Group 4:201905
201855 | Level 2 | Model Group:Group 4:201905
201856 | Level 2 | Model Group:Group 4:201905
201880 | Level 2 | Model Group:Group 4:201905
201884 | Level 2 | Model Group:Group 4:201905
201886 | Level 2 | Model Group:Group 4:201905
201887 | Level 2 | Model Group:Group 4:201905
201888 | Level 2 | Model Group:Group 4:201905
203664 | L 3 | Model Group:Group 4:204045
203666 | L 3 | Model Group:Group 4:204045
203668 | L 3 | Model Group:Group 4:204045
203669 | L 3 | Model Group:Group 4:204045
203670 | L 3 | Model Group:Group 4:204045
203687 | L 3 | Model Group:Group 4:204045
203689 | L 3 | Model Group:Group 4:204045
203693 | L 3 | Model Group:Group 4:204045
203694 | L 3 | Model Group:Group 4:204045
203695 | L 3 | Model Group:Group 4:204045
203712 | L 3 | Model Group:Group 4:204045
203730 | L 3 | Model Group:Group 4:204045
203714 | L 3 | Model Group:Group 4:204045
203724 | L 3 | Model Group:Group 4:204045
203731 | L 3 | Model Group:Group 4:204045
203738 | L 3 | Model Group:Group 4:204045
203756 | L 3 | Model Group:Group 4:204045
203740 | L 3 | Model Group:Group 4:204045
203750 | L 3 | Model Group:Group 4:204045
203757 | L 3 | Model Group:Group 4:204045
203764 | L 3 | Model Group:Group 4:204045
203766 | L 3 | Model Group:Group 4:204045
203768 | L 3 | Model Group:Group 4:204045
203770 | L 3 | Model Group:Group 4:204045
203772 | L 3 | Model Group:Group 4:204045
203774 | L 3 | Model Group:Group 4:204045
203776 | L 3 | Model Group:Group 4:204045
203778 | L 3 | Model Group:Group 4:204045
203780 | L 3 | Model Group:Group 4:204045
203782 | L 3 | Model Group:Group 4:204045
203964 | L 3 | Model Group:Group 4:204045
203784 | L 3 | Model Group:Group 4:204045
203785 | L 3 | Model Group:Group 4:204045
203786 | L 3 | Model Group:Group 4:204045
203787 | L 3 | Model Group:Group 4:204045
203788 | L 3 | Model Group:Group 4:204045
203789 | L 3 | Model Group:Group 4:204045
203790 | L 3 | Model Group:Group 4:204045
203791 | L 3 | Model Group:Group 4:204045
203792 | L 3 | Model Group:Group 4:204045
203793 | L 3 | Model Group:Group 4:204045
203965 | L 3 | Model Group:Group 4:204045
203847 | L 3 | Model Group:Group 4:204045
203851 | L 3 | Model Group:Group 4:204045
203853 | L 3 | Model Group:Group 4:204045
203855 | L 3 | Model Group:Group 4:204045
203856 | L 3 | Model Group:Group 4:204045
203857 | L 3 | Model Group:Group 4:204045
203858 | L 3 | Model Group:Group 4:204045
203881 | L 3 | Model Group:Group 4:204045
203883 | L 3 | Model Group:Group 4:204045
203885 | L 3 | Model Group:Group 4:204045
203887 | L 3 | Model Group:Group 4:204045
203889 | L 3 | Model Group:Group 4:204045
203891 | L 3 | Model Group:Group 4:204045
203893 | L 3 | Model Group:Group 4:204045
203895 | L 3 | Model Group:Group 4:204045
203897 | L 3 | Model Group:Group 4:204045
203899 | L 3 | Model Group:Group 4:204045
203967 | L 3 | Model Group:Group 4:204045
203901 | L 3 | Model Group:Group 4:204045
203902 | L 3 | Model Group:Group 4:204045
203903 | L 3 | Model Group:Group 4:204045
203904 | L 3 | Model Group:Group 4:204045
203905 | L 3 | Model Group:Group 4:204045
203906 | L 3 | Model Group:Group 4:204045
203907 | L 3 | Model Group:Group 4:204045
203908 | L 3 | Model Group:Group 4:204045
203909 | L 3 | Model Group:Group 4:204045
203910 | L 3 | Model Group:Group 4:204045
203968 | L 3 | Model Group:Group 4:204045
203986 | L 3 | Model Group:Group 4:204045
203988 | L 3 | Model Group:Group 4:204045
203992 | L 3 | Model Group:Group 4:204045
203994 | L 3 | Model Group:Group 4:204045
203995 | L 3 | Model Group:Group 4:204045
203996 | L 3 | Model Group:Group 4:204045
203997 | L 3 | Model Group:Group 4:204045
204020 | L 3 | Model Group:Group 4:204045
204024 | L 3 | Model Group:Group 4:204045
204026 | L 3 | Model Group:Group 4:204045
204027 | L 3 | Model Group:Group 4:204045
204028 | L 3 | Model Group:Group 4:204045
204401 | L 5 | Model Group:Group 4:204782
204403 | L 5 | Model Group:Group 4:204782
204405 | L 5 | Model Group:Group 4:204782
204406 | L 5 | Model Group:Group 4:204782
204407 | L 5 | Model Group:Group 4:204782
204424 | L 5 | Model Group:Group 4:204782
204426 | L 5 | Model Group:Group 4:204782
204430 | L 5 | Model Group:Group 4:204782
204431 | L 5 | Model Group:Group 4:204782
204432 | L 5 | Model Group:Group 4:204782
204449 | L 5 | Model Group:Group 4:204782
204467 | L 5 | Model Group:Group 4:204782
204451 | L 5 | Model Group:Group 4:204782
204461 | L 5 | Model Group:Group 4:204782
204468 | L 5 | Model Group:Group 4:204782
204475 | L 5 | Model Group:Group 4:204782
204493 | L 5 | Model Group:Group 4:204782
204477 | L 5 | Model Group:Group 4:204782
204487 | L 5 | Model Group:Group 4:204782
204494 | L 5 | Model Group:Group 4:204782
204501 | L 5 | Model Group:Group 4:204782
204503 | L 5 | Model Group:Group 4:204782
204505 | L 5 | Model Group:Group 4:204782
204507 | L 5 | Model Group:Group 4:204782
204509 | L 5 | Model Group:Group 4:204782
204511 | L 5 | Model Group:Group 4:204782
204513 | L 5 | Model Group:Group 4:204782
204515 | L 5 | Model Group:Group 4:204782
204517 | L 5 | Model Group:Group 4:204782
204519 | L 5 | Model Group:Group 4:204782
204701 | L 5 | Model Group:Group 4:204782
204521 | L 5 | Model Group:Group 4:204782
204522 | L 5 | Model Group:Group 4:204782
204523 | L 5 | Model Group:Group 4:204782
204524 | L 5 | Model Group:Group 4:204782
204525 | L 5 | Model Group:Group 4:204782
204526 | L 5 | Model Group:Group 4:204782
204527 | L 5 | Model Group:Group 4:204782
204528 | L 5 | Model Group:Group 4:204782
204529 | L 5 | Model Group:Group 4:204782
204530 | L 5 | Model Group:Group 4:204782
204702 | L 5 | Model Group:Group 4:204782
204584 | L 5 | Model Group:Group 4:204782
204588 | L 5 | Model Group:Group 4:204782
204590 | L 5 | Model Group:Group 4:204782
204592 | L 5 | Model Group:Group 4:204782
204593 | L 5 | Model Group:Group 4:204782
204594 | L 5 | Model Group:Group 4:204782
204595 | L 5 | Model Group:Group 4:204782
204618 | L 5 | Model Group:Group 4:204782
204620 | L 5 | Model Group:Group 4:204782
204622 | L 5 | Model Group:Group 4:204782
204624 | L 5 | Model Group:Group 4:204782
204626 | L 5 | Model Group:Group 4:204782
204628 | L 5 | Model Group:Group 4:204782
204630 | L 5 | Model Group:Group 4:204782
204632 | L 5 | Model Group:Group 4:204782
204634 | L 5 | Model Group:Group 4:204782
204636 | L 5 | Model Group:Group 4:204782
204704 | L 5 | Model Group:Group 4:204782
204638 | L 5 | Model Group:Group 4:204782
204639 | L 5 | Model Group:Group 4:204782
204640 | L 5 | Model Group:Group 4:204782
204641 | L 5 | Model Group:Group 4:204782
204642 | L 5 | Model Group:Group 4:204782
204643 | L 5 | Model Group:Group 4:204782
204644 | L 5 | Model Group:Group 4:204782
204645 | L 5 | Model Group:Group 4:204782
204646 | L 5 | Model Group:Group 4:204782
204647 | L 5 | Model Group:Group 4:204782
204705 | L 5 | Model Group:Group 4:204782
204723 | L 5 | Model Group:Group 4:204782
204725 | L 5 | Model Group:Group 4:204782
204729 | L 5 | Model Group:Group 4:204782
204731 | L 5 | Model Group:Group 4:204782
204732 | L 5 | Model Group:Group 4:204782
204733 | L 5 | Model Group:Group 4:204782
204734 | L 5 | Model Group:Group 4:204782
204757 | L 5 | Model Group:Group 4:204782
204761 | L 5 | Model Group:Group 4:204782
204763 | L 5 | Model Group:Group 4:204782
204764 | L 5 | Model Group:Group 4:204782
204765 | L 5 | Model Group:Group 4:204782
204859 | L 7 | Model Group:Group 4:205240
204861 | L 7 | Model Group:Group 4:205240
204863 | L 7 | Model Group:Group 4:205240
204864 | L 7 | Model Group:Group 4:205240
204865 | L 7 | Model Group:Group 4:205240
204882 | L 7 | Model Group:Group 4:205240
204884 | L 7 | Model Group:Group 4:205240
204888 | L 7 | Model Group:Group 4:205240
204889 | L 7 | Model Group:Group 4:205240
204890 | L 7 | Model Group:Group 4:205240
204907 | L 7 | Model Group:Group 4:205240
204925 | L 7 | Model Group:Group 4:205240
204909 | L 7 | Model Group:Group 4:205240
204919 | L 7 | Model Group:Group 4:205240
204926 | L 7 | Model Group:Group 4:205240
204933 | L 7 | Model Group:Group 4:205240
204951 | L 7 | Model Group:Group 4:205240
204935 | L 7 | Model Group:Group 4:205240
204945 | L 7 | Model Group:Group 4:205240
204952 | L 7 | Model Group:Group 4:205240
204959 | L 7 | Model Group:Group 4:205240
204961 | L 7 | Model Group:Group 4:205240
204963 | L 7 | Model Group:Group 4:205240
204965 | L 7 | Model Group:Group 4:205240
204967 | L 7 | Model Group:Group 4:205240
204969 | L 7 | Model Group:Group 4:205240
204971 | L 7 | Model Group:Group 4:205240
204973 | L 7 | Model Group:Group 4:205240
204975 | L 7 | Model Group:Group 4:205240
204977 | L 7 | Model Group:Group 4:205240
205159 | L 7 | Model Group:Group 4:205240
204979 | L 7 | Model Group:Group 4:205240
204980 | L 7 | Model Group:Group 4:205240
204981 | L 7 | Model Group:Group 4:205240
204982 | L 7 | Model Group:Group 4:205240
204983 | L 7 | Model Group:Group 4:205240
204984 | L 7 | Model Group:Group 4:205240
204985 | L 7 | Model Group:Group 4:205240
204986 | L 7 | Model Group:Group 4:205240
204987 | L 7 | Model Group:Group 4:205240
204988 | L 7 | Model Group:Group 4:205240
205160 | L 7 | Model Group:Group 4:205240
205042 | L 7 | Model Group:Group 4:205240
205046 | L 7 | Model Group:Group 4:205240
205048 | L 7 | Model Group:Group 4:205240
205050 | L 7 | Model Group:Group 4:205240
205051 | L 7 | Model Group:Group 4:205240
205052 | L 7 | Model Group:Group 4:205240
205053 | L 7 | Model Group:Group 4:205240
205076 | L 7 | Model Group:Group 4:205240
205078 | L 7 | Model Group:Group 4:205240
205080 | L 7 | Model Group:Group 4:205240
205082 | L 7 | Model Group:Group 4:205240
205084 | L 7 | Model Group:Group 4:205240
205086 | L 7 | Model Group:Group 4:205240
205088 | L 7 | Model Group:Group 4:205240
205090 | L 7 | Model Group:Group 4:205240
205092 | L 7 | Model Group:Group 4:205240
205094 | L 7 | Model Group:Group 4:205240
205162 | L 7 | Model Group:Group 4:205240
205096 | L 7 | Model Group:Group 4:205240
205097 | L 7 | Model Group:Group 4:205240
205098 | L 7 | Model Group:Group 4:205240
205099 | L 7 | Model Group:Group 4:205240
205100 | L 7 | Model Group:Group 4:205240
205101 | L 7 | Model Group:Group 4:205240
205102 | L 7 | Model Group:Group 4:205240
205103 | L 7 | Model Group:Group 4:205240
205104 | L 7 | Model Group:Group 4:205240
205105 | L 7 | Model Group:Group 4:205240
205163 | L 7 | Model Group:Group 4:205240
205181 | L 7 | Model Group:Group 4:205240
205183 | L 7 | Model Group:Group 4:205240
205187 | L 7 | Model Group:Group 4:205240
205189 | L 7 | Model Group:Group 4:205240
205190 | L 7 | Model Group:Group 4:205240
205191 | L 7 | Model Group:Group 4:205240
205192 | L 7 | Model Group:Group 4:205240
205215 | L 7 | Model Group:Group 4:205240
205219 | L 7 | Model Group:Group 4:205240
205221 | L 7 | Model Group:Group 4:205240
205222 | L 7 | Model Group:Group 4:205240
205223 | L 7 | Model Group:Group 4:205240
205299 | L 9
205301 | L 9
205303 | L 9
205304 | L 9
205305 | L 9
205322 | L 9
205324 | L 9
205328 | L 9
205329 | L 9
205330 | L 9
205347 | L 9 | Model Group:Array Group 2:207312
205365 | L 9 | Model Group:Array Group 2:207312
205349 | L 9 | Model Group:Array Group 2:207312
205359 | L 9 | Model Group:Array Group 2:207312
205366 | L 9 | Model Group:Array Group 2:207312
205373 | L 9 | Model Group:Array Group 2:207312
205391 | L 9 | Model Group:Array Group 2:207312
205375 | L 9 | Model Group:Array Group 2:207312
205385 | L 9 | Model Group:Array Group 2:207312
205392 | L 9 | Model Group:Array Group 2:207312
205399 | L 9
205401 | L 9
205403 | L 9
205405 | L 9
205407 | L 9
205409 | L 9
205411 | L 9
205413 | L 9
205415 | L 9
205417 | L 9
205599 | L 9
205419 | L 9
205420 | L 9
205421 | L 9
205422 | L 9
205423 | L 9
205424 | L 9
205425 | L 9
205426 | L 9
205427 | L 9
205428 | L 9
205600 | L 9
205482 | L 9
205486 | L 9
205488 | L 9
205490 | L 9
205491 | L 9
205492 | L 9
205493 | L 9
205516 | L 9
205518 | L 9
205520 | L 9
205522 | L 9
205524 | L 9
205526 | L 9
205528 | L 9
205530 | L 9
205532 | L 9
205534 | L 9
205602 | L 9
205536 | L 9
205537 | L 9
205538 | L 9
205539 | L 9
205540 | L 9
205541 | L 9
205542 | L 9
205543 | L 9
205544 | L 9
205545 | L 9
205603 | L 9
205621 | L 9
205623 | L 9
205627 | L 9
205629 | L 9
205630 | L 9
205631 | L 9
205632 | L 9
205655 | L 9
205659 | L 9
205661 | L 9
205662 | L 9
205663 | L 9
207316 | L 11
207334 | L 11
207318 | L 11
207328 | L 11
207335 | L 11
207342 | L 11
207360 | L 11
207344 | L 11
207354 | L 11
207361 | L 11

# IfcRailing: Railing:Glass Panel - Bottom Fill (77)
Classification: C2010400 Stair Handrails/Balustrades (Uniformat); Material: Glass, alum - color
Pset_RailingCommon - IsExternal: no; Reference: Glass Panel - Bottom Fill; Height: 3 ft
Name (Railing:Glass Panel - Bottom Fill:...) | In
209652 | L 11
188704 | Level 1
188708 | Level 1
188787 | Level 1
188791 | Level 1
189280 | L 1
189284 | L 1
189288 | L 1
189292 | L 1
189534 | Level 2
189538 | Level 2
189542 | Level 2
189546 | Level 2
190282 | L 2
190286 | L 2
190290 | L 2
190294 | L 2
190538 | L 3
190542 | L 3
190546 | L 3
190550 | L 3
190786 | L 4
190790 | L 4
190794 | L 4
190798 | L 4
191041 | L 5
191045 | L 5
191049 | L 5
191053 | L 5
191268 | L 6
191272 | L 6
191276 | L 6
191280 | L 6
191484 | L 7
191488 | L 7
191492 | L 7
191496 | L 7
191703 | L 8
191707 | L 8
191711 | L 8
191715 | L 8
192364 | Level 2
192455 | Level 2
192503 | L 3
192529 | L 3
192589 | L 5
192609 | L 5
192672 | L 7
192692 | L 7
192760 | L 9
192780 | L 9
192964 | L 1
193051 | L 2
193103 | L 4
193155 | L 6
193197 | L 8
193367 | L 1
193387 | L 2
193407 | L 4
193427 | L 6
193447 | L 8
202826 | Level 2 | Group: Model Group:Group 4:201905
204054 | L 3 | Group: Model Group:Group 4:204045
204791 | L 5 | Group: Model Group:Group 4:204782
205249 | L 7 | Group: Model Group:Group 4:205240
205689 | L 9
206163 | L 9
206167 | L 9
206321 | L 9
206325 | L 9
206617 | L 10
206621 | L 10
206845 | L 10
206849 | L 10
209572 | L 11
209590 | L 11
209618 | L 10

# IfcSlab: Floor:Generic - 12" (26)
PredefinedType: FLOOR; Classification: B1010 Floor Construction (Uniformat); Material: Concrete, Cast-in-Place gray 1 ft
Pset_SlabCommon - IsExternal: no; Reference: Generic - 12"; LoadBearing: no; ThermalTransmittance: 3.43176 kg/K/s3; PitchAngle: 0 deg
Name (Floor:Generic - 12":...) | In
188766 | L 1
189007 | Level 2
189023 | Level 2
189039 | L 2
189669 | L 3
189678 | L 3
189694 | L 4
189727 | L 5
189736 | L 5
189745 | L 6
189772 | L 6
189781 | L 6
189790 | L 6
189815 | L 6
189824 | L 6
191851 | Level 1
193487 | Level 2
201482 | L 3
203648 | L 5 | Group: Model Group:Array Group 1:204379
204385 | L 7 | Group: Model Group:Array Group 1:204817
204843 | L 9 | Group: Model Group:Array Group 1:205275
205283 | L 9
205753 | L 8
205764 | L 8
205772 | L 8
207603 | L 12

# IfcStair: Assembled Stair:7" max riser 11" tread:168814 (15)
Classification: C Interiors (Uniformat)
Pset_StairCommon - Reference: 7" max riser 11" tread; IsExternal: no; NumberOfRiser: 9; RiserHeight: 0.555556 ft; TreadLength: 0.916667 ft
Name (Assembled Stair:Stair:...) | In | NumberOfTreads
188699 | Level 1 | 8
188782 | Level 1 | 8
189066 | L 1 | 16
189410 | Level 2 | 16
190141 | L 2 | 16
190399 | L 3 | 16
190655 | L 4 | 16
190903 | L 5 | 16
191158 | L 6 | 16
191385 | L 7 | 16
191601 | L 8 | 16
206083 | L 9 | 8
206209 | L 9 | 8
206445 | L 10 | 8
206840 | L 10 | 8

# IfcStairFlight: Assembled Stair:7" max riser 11" tread:168814 (24)
NumberOfRiser: 9; NumberOfTreads: 8; RiserHeight: 0.555556 ft; TreadLength: 0.916667 ft; Classification: C Interiors (Uniformat)
Pset_StairFlightCommon - Reference: 2" Tread 1" Nosing 1/4" Riser; NumberOfRiser: 9; RiserHeight: 0.555556 ft; TreadLength: 0.916667 ft; TreadLengthAtOffset: 0.916667 ft; NosingLength: 0.0833333 ft; WalkingLineOffset: 1.75 ft; WaistThickness: 3.5 ft
Name (Assembled Stair:Stair:...) | In | NumberOfTreads
188699 Run 1 | Level 1 | 8
188782 Run 1 | Level 1 | 8
189066 Run 1 | L 1 | 16
189066 Run 2 | L 1 | 16
189410 Run 1 | Level 2 | 16
189410 Run 2 | Level 2 | 16
190141 Run 1 | L 2 | 16
190141 Run 2 | L 2 | 16
190399 Run 1 | L 3 | 16
190399 Run 2 | L 3 | 16
190655 Run 1 | L 4 | 16
190655 Run 2 | L 4 | 16
190903 Run 1 | L 5 | 16
190903 Run 2 | L 5 | 16
191158 Run 1 | L 6 | 16
191158 Run 2 | L 6 | 16
191385 Run 1 | L 7 | 16
191385 Run 2 | L 7 | 16
191601 Run 1 | L 8 | 16
191601 Run 2 | L 8 | 16
206083 Run 1 | L 9 | 8
206209 Run 1 | L 9 | 8
206445 Run 1 | L 10 | 8
206840 Run 1 | L 10 | 8

# IfcWallStandardCase: Basic Wall:Generic - 6" (39)
Type - PredefinedType: STANDARD; Material: Default Wall 0.5 ft
Classification: B2010 Exterior Walls (Uniformat)
Pset_WallCommon - LoadBearing: no; ExtendToStructure: no; IsExternal: yes; Reference: Generic - 6"
Name (Basic Wall:Generic - 6":...) | In | Group
195196 | Level 1
195378 | Level 1
195446 | Level 1
198686 | Level 1 | Model Group:Group 3:200611
198800 | Level 1 | Model Group:Group 3:200611
198908 | Level 1 | Model Group:Group 3:200611
199025 | Level 1 | Model Group:Group 3:200611
199107 | Level 1 | Model Group:Group 3:200611
199174 | Level 1 | Model Group:Group 3:200611
201832 | Level 2 | Model Group:Group 4:201905
201833 | Level 2 | Model Group:Group 4:201905
201834 | Level 2 | Model Group:Group 4:201905
201835 | Level 2 | Model Group:Group 4:201905
201836 | Level 2 | Model Group:Group 4:201905
201837 | Level 2 | Model Group:Group 4:201905
203979 | L 3 | Model Group:Group 4:204045
203980 | L 3 | Model Group:Group 4:204045
203981 | L 3 | Model Group:Group 4:204045
203982 | L 3 | Model Group:Group 4:204045
203983 | L 3 | Model Group:Group 4:204045
203984 | L 3 | Model Group:Group 4:204045
204716 | L 5 | Model Group:Group 4:204782
204717 | L 5 | Model Group:Group 4:204782
204718 | L 5 | Model Group:Group 4:204782
204719 | L 5 | Model Group:Group 4:204782
204720 | L 5 | Model Group:Group 4:204782
204721 | L 5 | Model Group:Group 4:204782
205174 | L 7 | Model Group:Group 4:205240
205175 | L 7 | Model Group:Group 4:205240
205176 | L 7 | Model Group:Group 4:205240
205177 | L 7 | Model Group:Group 4:205240
205178 | L 7 | Model Group:Group 4:205240
205179 | L 7 | Model Group:Group 4:205240
205614 | L 9
205615 | L 9
205616 | L 9
205617 | L 9
205618 | L 9
205619 | L 9

# IfcWallStandardCase: Basic Wall:Generic - 8" (2)
In: Level 1
Type - PredefinedType: STANDARD; Material: Default Wall 0.666667 ft
Classification: B2010 Exterior Walls (Uniformat)
Pset_WallCommon - LoadBearing: no; Reference: Generic - 8"; ExtendToStructure: no; IsExternal: yes
Name (Basic Wall:Generic - 8":...)
193874
194022
